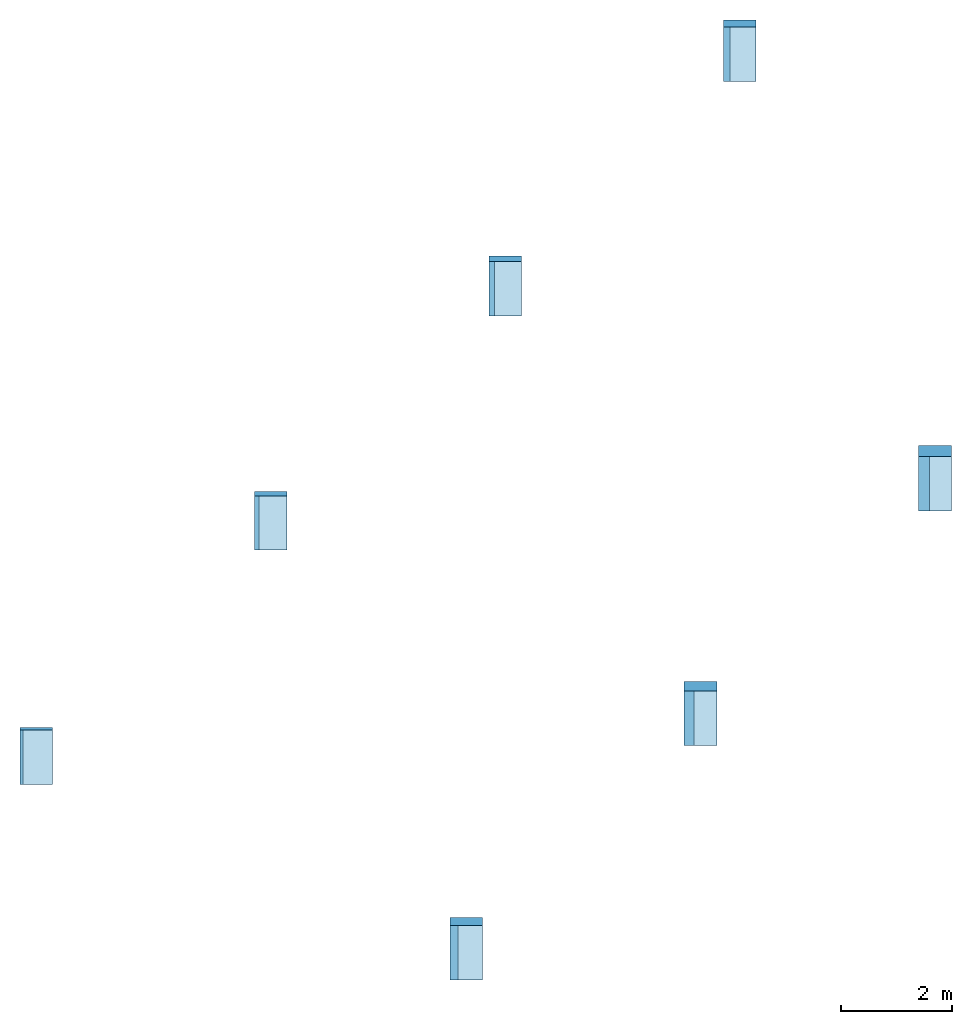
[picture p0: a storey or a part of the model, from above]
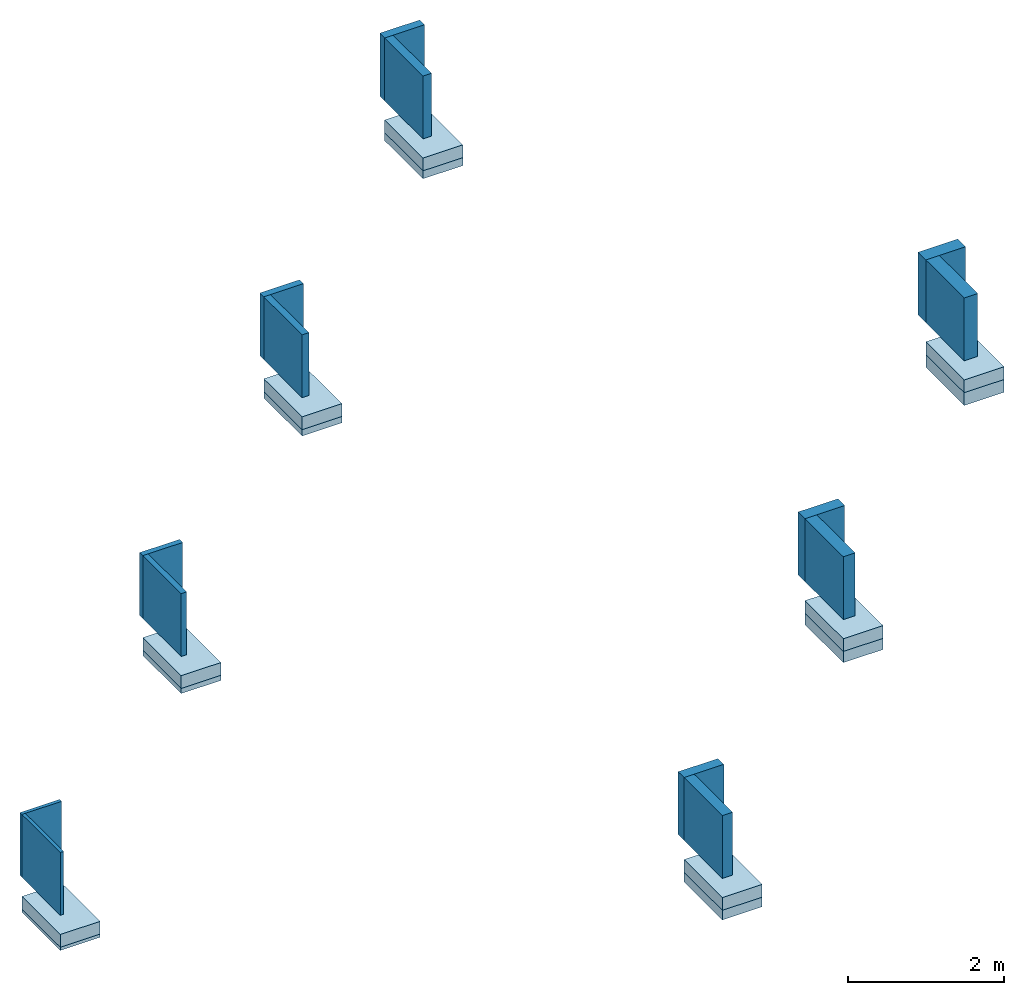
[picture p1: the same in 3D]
Properties of the parts of a building model (IFC2X3), part 1 of 2

# File
Description: ViewDefinition [CoordinationView]
File name: 012345
Time: 2023-01-18T09:47:16
Written by: The EXPRESS Data Manager Version 5.02.0100.07 : 28 Aug 2013
Made in: 21.1.70.21 - Exporter 21.1.70.21 - Alternate UI 21.1.70.21
Comment: STEP Physical File produced by: The EXPRESS Data Manager Version 5.02.0100.07 : 28 Aug 2013 * Module: EDMstepFileFactory/EDMstandAlone * Creation date: Wed Jan 18 09:47:16 2023 * Host: BIM-LT03 * Database: C:\Users\DONNEE~1\AppData\Local\Temp\6dfd9f73-01cb-4fe2-bb7c-203e315a706e\23b874d5-0400-469c-8f44-2d7696e1532f\ifc * Database version: 5507 * Database creation date: Wed Jan 18 09:47:14 2023 * Schema: IFC2X3 * Model: DataRepository.ifc * Model creation date: Wed Jan 18 09:47:15 2023 * Header model: DataRepository.ifc_HeaderModel * Header model creation date: Wed Jan 18 09:47:15 2023 * EDMuser: sdai-user * EDMgroup: sdai-group * License ID and type: 5605 : Permanent license. Expiry date: * EDMstepFileFactory options: 020000

# IfcProject, 012345
LongName: Cadix Project Naam; Phase: Cadix leeg V2.0

# IfcSite, Default
RefLatitude: 52, 3, 20, 225830; RefLongitude: 5, 6, 28, 692855; RefElevation: 0 mm
Pset_ProductRequirements - Category: Project Information

# IfcBuilding
Pset_BuildingCommon - NumberOfStoreys: 2
Pset_ProductRequirements - Category: Project Information

# IfcBuildingStorey: Level:niveau (2)
Pset_ProductRequirements - Category: Levels
Name | LongName = Pset_AirSideSystemInformation, Name = Pset_ProductRequirements, Name | Elevation (mm)
00 begane grond | 00 begane grond | -2.7707e-11
01 eerste verdieping | 01 eerste verdieping | 985

# IfcCovering: Compound Ceiling:NLRS_45_CEI_Heraklith - Heratekta+ 050x590x985mm, Compound Ceiling:NLRS_45_CEI_Heraklith - Heratekta+ 050x590x985mm:915812
In: 01 eerste verdieping
Type - PredefinedType: CEILING
Type - Pset_ConcreteElementGeneral - FireRating: REI 120/180 mits verwerkt.....
Type - Pset_CoveringCommon - Reference: Compound Ceiling:NLRS_45_CEI_Heraklith - Heratekta+ 050x590x985mm; FireRating: REI 120/180 mits verwerkt.....; TotalThickness: 50 mm
Type - Pset_ElementShading - Roughness: 914.4 mm
Type - Pset_ManufacturerTypeInformation - Manufacturer: Knauf Insulation B.V.
Type - Pset_ProductRequirements - Category: Ceilings
Type - Pset_QuantityTakeOff - Reference: Compound Ceiling:NLRS_45_CEI_Heraklith - Heratekta+ 050x590x985mm
Type - Ceiling Schedule LOD200 - Assembly Code: 45; Type Image: Raster image: Heraklith Heratekta.jpg; Model: Heraklith® | Heratekta+ is een houtwolcementpaneel gecombineerd met een EPS-plaat.; Manufacturer: Knauf Insulation B.V.; URL: www.heraklith.nl; Description: Heratekta+ - 50mm; phone: +31(0)162-421245; email: customerservice.nl@knaufinsulation.com; product URL: https://heraklith.nl/houtwol-producten/heratekta-met-EPS; warmteweerstand: 1,40 (m2.K/W); NLRS_C_Code_Brandklasse: B-s1,d0; brandweerstand: n.v.t; geluidsabsorbtie: 0,30; DoP: 4010_HERATEKTA+; NLRS_C_content_creator: Knauf Insulation; NLRS_C_content_versie: V1.0
Type - Pset_Ceiling Schedule LOD400 - gewicht KG/M2: 9; Assembly Code: 45; Type Image: Raster image: Heraklith Heratekta.jpg; Model: Heraklith® | Heratekta+ is een houtwolcementpaneel gecombineerd met een EPS-plaat.; Manufacturer: Knauf Insulation B.V.; URL: www.heraklith.nl; Description: Heratekta+ - 50mm; phone: +31(0)162-421245; email: customerservice.nl@knaufinsulation.com; product URL: https://heraklith.nl/houtwol-producten/heratekta-met-EPS; warmteweerstand: 1,40 (m2.K/W); NLRS_C_Code_Brandklasse: B-s1,d0; brandweerstand: n.v.t; geluidsabsorbtie: 0,30; DoP: 4010_HERATEKTA+; NLRS_C_content_creator: Knauf Insulation; NLRS_C_content_versie: V1.0; panelen per pallet: 44; pallet m2: 25.57 m2; vezelbreedte: standaard 2mm optie: 1mm; kleur: standaard naturel optie: Wit (RAL9003) / RAL; Druksterkte kPa: 40; Chloride gehalte: Cl1; Tolerantie: Dikte (T): (T1) +3/-2; Tolerantie: Lengte (L): (L2) +3/-5; Tolerantie: Breedte (W): (W1) +3/-3; Tolerantie: Haaksheid (S): (S1) ≤4; Tolerantie: Vlakheid (P): (P1) ≤6; Randafwerking: Isolatie: tand en groef; Randafwerking: Houtwol: Facet: 5mm; CE-codering: WW-C/2 EPS-EN13168-L2-W1-S1-T1-P1-CS(10/Y)40-Cl1
Classification: 45 (Uniformat); Material: Heraklith® I Heratekta - EPS60-SE 40 mm, Heraklith® | Heratekta - Houtwollaag - 985x590mm 10 mm
Pset_CoveringCommon - Finish: Heraklith® | Heratekta - Houtwollaag - 985x590mm;
Ceiling Schedule LOD200 - Type: Compound Ceiling: NLRS_45_CEI_Heraklith - Heratekta+ 050x590x985mm
Pset_Ceiling Schedule LOD400 - Type: Compound Ceiling: NLRS_45_CEI_Heraklith - Heratekta+ 050x590x985mm

# IfcCovering: Compound Ceiling:NLRS_45_CEI_Heraklith - Heratekta+ 080x590x985mm, Compound Ceiling:NLRS_45_CEI_Heraklith - Heratekta+ 080x590x985mm:930047
In: 01 eerste verdieping
Type - PredefinedType: CEILING
Type - Pset_CoveringCommon - Reference: Compound Ceiling:NLRS_45_CEI_Heraklith - Heratekta+ 080x590x985mm; TotalThickness: 80 mm
Type - Pset_ElementShading - Roughness: 914.4 mm
Type - Pset_ManufacturerTypeInformation - Manufacturer: Knauf Insulation B.V.
Type - Pset_ProductRequirements - Category: Ceilings
Type - Pset_QuantityTakeOff - Reference: Compound Ceiling:NLRS_45_CEI_Heraklith - Heratekta+ 080x590x985mm
Type - Ceiling Schedule LOD200 - Assembly Code: 45; Type Image: Raster image: Heraklith Heratekta.jpg; Model: Heraklith® | Heratekta+ is een houtwolcementpaneel gecombineerd met een EPS-plaat.; Manufacturer: Knauf Insulation B.V.; URL: www.heraklith.nl; Description: Heratekta+ - 80mm; phone: +31(0)162-421245; email: customerservice.nl@knaufinsulation.com; product URL: https://heraklith.nl/houtwol-producten/heratekta-met-EPS; warmteweerstand: 2,35 (m2.K/W); NLRS_C_Code_Brandklasse: B-s1,d0; brandweerstand: n.v.t; geluidsabsorbtie: 0,30; DoP: 4010_HERATEKTA+; NLRS_C_content_creator: Knauf Insulation; NLRS_C_content_versie: V1.0
Type - Pset_Ceiling Schedule LOD400 - Assembly Code: 45; Type Image: Raster image: Heraklith Heratekta.jpg; Model: Heraklith® | Heratekta+ is een houtwolcementpaneel gecombineerd met een EPS-plaat.; Manufacturer: Knauf Insulation B.V.; URL: www.heraklith.nl; Description: Heratekta+ - 80mm; phone: +31(0)162-421245; email: customerservice.nl@knaufinsulation.com; product URL: https://heraklith.nl/houtwol-producten/heratekta-met-EPS; warmteweerstand: 2,35 (m2.K/W); NLRS_C_Code_Brandklasse: B-s1,d0; brandweerstand: n.v.t; geluidsabsorbtie: 0,30; DoP: 4010_HERATEKTA+; NLRS_C_content_creator: Knauf Insulation; NLRS_C_content_versie: V1.0; gewicht KG/M2: 9.4; panelen per pallet: 26; pallet m2: 15.11 m2; vezelbreedte: standaard 2mm optie: 1mm; kleur: standaard naturel optie: Wit (RAL9003) / RAL; Druksterkte kPa: 40; Chloride gehalte: Cl1; Tolerantie: Dikte (T): (T1) +3/-2; Tolerantie: Lengte (L): (L2) +3/-5; Tolerantie: Breedte (W): (W1) +3/-3; Tolerantie: Haaksheid (S): (S1) ≤4; Tolerantie: Vlakheid (P): (P1) ≤6; Randafwerking: Isolatie: tand en groef; Randafwerking: Houtwol: Facet: 5mm; CE-codering: WW-C/2 EPS-EN13168-L2-W1-S1-T1-P1-CS(10/Y)40-Cl1
Classification: 45 (Uniformat); Material: Heraklith® I Heratekta - EPS60-SE 70 mm, Heraklith® | Heratekta - Houtwollaag - 985x590mm 10 mm
Pset_CoveringCommon - Finish: Heraklith® | Heratekta - Houtwollaag - 985x590mm;
Ceiling Schedule LOD200 - Type: Compound Ceiling: NLRS_45_CEI_Heraklith - Heratekta+ 080x590x985mm
Pset_Ceiling Schedule LOD400 - Type: Compound Ceiling: NLRS_45_CEI_Heraklith - Heratekta+ 080x590x985mm

# IfcCovering: Compound Ceiling:NLRS_45_CEI_Heraklith - Heratekta+ 100x590x985mm, Compound Ceiling:NLRS_45_CEI_Heraklith - Heratekta+ 100x590x985mm:930187
In: 01 eerste verdieping
Type - PredefinedType: CEILING
Type - Pset_CoveringCommon - Reference: Compound Ceiling:NLRS_45_CEI_Heraklith - Heratekta+ 100x590x985mm; TotalThickness: 100 mm
Type - Pset_ElementShading - Roughness: 914.4 mm
Type - Pset_ManufacturerTypeInformation - Manufacturer: Knauf Insulation B.V.
Type - Pset_ProductRequirements - Category: Ceilings
Type - Pset_QuantityTakeOff - Reference: Compound Ceiling:NLRS_45_CEI_Heraklith - Heratekta+ 100x590x985mm
Type - Ceiling Schedule LOD200 - Assembly Code: 45; Type Image: Raster image: Heraklith Heratekta.jpg; Model: Heraklith® | Heratekta+ is een houtwolcementpaneel gecombineerd met een EPS-plaat.; Manufacturer: Knauf Insulation B.V.; URL: www.heraklith.nl; Description: Heratekta+ - 100mm; phone: +31(0)162-421245; email: customerservice.nl@knaufinsulation.com; product URL: https://heraklith.nl/houtwol-producten/heratekta-met-EPS; warmteweerstand: 3,00 (m2.K/W); NLRS_C_Code_Brandklasse: B-s1,d0; brandweerstand: n.v.t; geluidsabsorbtie: 0,30; DoP: 4010_HERATEKTA+; NLRS_C_content_creator: Knauf Insulation; NLRS_C_content_versie: V1.0
Type - Pset_Ceiling Schedule LOD400 - Assembly Code: 45; Type Image: Raster image: Heraklith Heratekta.jpg; Model: Heraklith® | Heratekta+ is een houtwolcementpaneel gecombineerd met een EPS-plaat.; Manufacturer: Knauf Insulation B.V.; URL: www.heraklith.nl; Description: Heratekta+ - 100mm; phone: +31(0)162-421245; email: customerservice.nl@knaufinsulation.com; product URL: https://heraklith.nl/houtwol-producten/heratekta-met-EPS; warmteweerstand: 3,00 (m2.K/W); NLRS_C_Code_Brandklasse: B-s1,d0; brandweerstand: n.v.t; geluidsabsorbtie: 0,30; DoP: 4010_HERATEKTA+; NLRS_C_content_creator: Knauf Insulation; NLRS_C_content_versie: V1.0; gewicht KG/M2: 9.7; panelen per pallet: 22; pallet m2: 12.79 m2; vezelbreedte: standaard 2mm optie: 1mm; kleur: standaard naturel optie: Wit (RAL9003) / RAL; Druksterkte kPa: 40; Chloride gehalte: Cl1; Tolerantie: Dikte (T): (T1) +3/-2; Tolerantie: Lengte (L): (L2) +3/-5; Tolerantie: Breedte (W): (W1) +3/-3; Tolerantie: Haaksheid (S): (S1) ≤4; Tolerantie: Vlakheid (P): (P1) ≤6; Randafwerking: Isolatie: tand en groef; Randafwerking: Houtwol: Facet: 5mm; CE-codering: WW-C/2 EPS-EN13168-L2-W1-S1-T1-P1-CS(10/Y)40-Cl1
Classification: 45 (Uniformat); Material: Heraklith® I Heratekta - EPS60-SE 90 mm, Heraklith® | Heratekta - Houtwollaag - 985x590mm 10 mm
Pset_CoveringCommon - Finish: Heraklith® | Heratekta - Houtwollaag - 985x590mm;
Ceiling Schedule LOD200 - Type: Compound Ceiling: NLRS_45_CEI_Heraklith - Heratekta+ 100x590x985mm
Pset_Ceiling Schedule LOD400 - Type: Compound Ceiling: NLRS_45_CEI_Heraklith - Heratekta+ 100x590x985mm

# IfcCovering: Compound Ceiling:NLRS_45_CEI_Heraklith - Heratekta+ 125x590x985mm, Compound Ceiling:NLRS_45_CEI_Heraklith - Heratekta+ 125x590x985mm:930347
In: 01 eerste verdieping
Type - PredefinedType: CEILING
Type - Pset_CoveringCommon - Reference: Compound Ceiling:NLRS_45_CEI_Heraklith - Heratekta+ 125x590x985mm; TotalThickness: 125 mm
Type - Pset_ElementShading - Roughness: 914.4 mm
Type - Pset_ManufacturerTypeInformation - Manufacturer: Knauf Insulation B.V.
Type - Pset_ProductRequirements - Category: Ceilings
Type - Pset_QuantityTakeOff - Reference: Compound Ceiling:NLRS_45_CEI_Heraklith - Heratekta+ 125x590x985mm
Type - Ceiling Schedule LOD200 - Assembly Code: 45; Type Image: Raster image: Heraklith Heratekta.jpg; Model: Heraklith® | Heratekta+ is een houtwolcementpaneel gecombineerd met een EPS-plaat.; Manufacturer: Knauf Insulation B.V.; URL: www.heraklith.nl; Description: Heratekta+ - 125mm; phone: +31(0)162-421245; email: customerservice.nl@knaufinsulation.com; product URL: https://heraklith.nl/houtwol-producten/heratekta-met-EPS; warmteweerstand: 3,80 (m2.K/W); NLRS_C_Code_Brandklasse: B-s1,d0; brandweerstand: n.v.t; geluidsabsorbtie: 0,30; DoP: 4010_HERATEKTA+; NLRS_C_content_creator: Knauf Insulation; NLRS_C_content_versie: V1.0
Type - Pset_Ceiling Schedule LOD400 - gewicht KG/M2: 10; Assembly Code: 45; Type Image: Raster image: Heraklith Heratekta.jpg; Model: Heraklith® | Heratekta+ is een houtwolcementpaneel gecombineerd met een EPS-plaat.; Manufacturer: Knauf Insulation B.V.; URL: www.heraklith.nl; Description: Heratekta+ - 125mm; phone: +31(0)162-421245; email: customerservice.nl@knaufinsulation.com; product URL: https://heraklith.nl/houtwol-producten/heratekta-met-EPS; warmteweerstand: 3,80 (m2.K/W); NLRS_C_Code_Brandklasse: B-s1,d0; brandweerstand: n.v.t; geluidsabsorbtie: 0,30; DoP: 4010_HERATEKTA+; NLRS_C_content_creator: Knauf Insulation; NLRS_C_content_versie: V1.0; panelen per pallet: 18; pallet m2: 10.46 m2; vezelbreedte: standaard 2mm optie: 1mm; kleur: standaard naturel optie: Wit (RAL9003) / RAL; Druksterkte kPa: 40; Chloride gehalte: Cl1; Tolerantie: Dikte (T): (T1) +3/-2; Tolerantie: Lengte (L): (L2) +3/-5; Tolerantie: Breedte (W): (W1) +3/-3; Tolerantie: Haaksheid (S): (S1) ≤4; Tolerantie: Vlakheid (P): (P1) ≤6; Randafwerking: Isolatie: tand en groef; Randafwerking: Houtwol: Facet: 5mm; CE-codering: WW-C/2 EPS-EN13168-L2-W1-S1-T1-P1-CS(10/Y)40-Cl1
Classification: 45 (Uniformat); Material: Heraklith® I Heratekta - EPS60-SE 115 mm, Heraklith® | Heratekta - Houtwollaag - 985x590mm 10 mm
Pset_CoveringCommon - Finish: Heraklith® | Heratekta - Houtwollaag - 985x590mm;
Ceiling Schedule LOD200 - Type: Compound Ceiling: NLRS_45_CEI_Heraklith - Heratekta+ 125x590x985mm
Pset_Ceiling Schedule LOD400 - Type: Compound Ceiling: NLRS_45_CEI_Heraklith - Heratekta+ 125x590x985mm

# IfcCovering: Compound Ceiling:NLRS_45_CEI_Heraklith - Heratekta+ 150x985x590mm, Compound Ceiling:NLRS_45_CEI_Heraklith - Heratekta+ 150x985x590mm:930587
In: 01 eerste verdieping
Type - PredefinedType: CEILING
Type - Pset_ConcreteElementGeneral - FireRating: REI 120/180 mits verwerkt.....
Type - Pset_CoveringCommon - Reference: Compound Ceiling:NLRS_45_CEI_Heraklith - Heratekta+ 150x985x590mm; FireRating: REI 120/180 mits verwerkt.....; TotalThickness: 150 mm
Type - Pset_ElementShading - Roughness: 914.4 mm
Type - Pset_ManufacturerTypeInformation - Manufacturer: Knauf Insulation B.V.
Type - Pset_ProductRequirements - Category: Ceilings
Type - Pset_QuantityTakeOff - Reference: Compound Ceiling:NLRS_45_CEI_Heraklith - Heratekta+ 150x985x590mm
Type - Ceiling Schedule LOD200 - Assembly Code: 45; Type Image: Raster image: Heraklith Heratekta.jpg; Model: Heraklith® | Heratekta+ is een houtwolcementpaneel gecombineerd met een EPS-plaat.; Manufacturer: Knauf Insulation B.V.; URL: www.heraklith.nl; Description: Heratekta+ - 150mm; phone: +31(0)162-421245; email: customerservice.nl@knaufinsulation.com; product URL: https://heraklith.nl/houtwol-producten/heratekta-met-EPS; warmteweerstand: 4,60 (m2.K/W); NLRS_C_Code_Brandklasse: B-s1,d0; brandweerstand: n.v.t; geluidsabsorbtie: 0,30; DoP: 4010_HERATEKTA+; NLRS_C_content_creator: Knauf Insulation; NLRS_C_content_versie: V1.0
Type - Pset_Ceiling Schedule LOD400 - Assembly Code: 45; Type Image: Raster image: Heraklith Heratekta.jpg; Model: Heraklith® | Heratekta+ is een houtwolcementpaneel gecombineerd met een EPS-plaat.; Manufacturer: Knauf Insulation B.V.; URL: www.heraklith.nl; Description: Heratekta+ - 150mm; phone: +31(0)162-421245; email: customerservice.nl@knaufinsulation.com; product URL: https://heraklith.nl/houtwol-producten/heratekta-met-EPS; warmteweerstand: 4,60 (m2.K/W); NLRS_C_Code_Brandklasse: B-s1,d0; brandweerstand: n.v.t; geluidsabsorbtie: 0,30; DoP: 4010_HERATEKTA+; NLRS_C_content_creator: Knauf Insulation; NLRS_C_content_versie: V1.0; gewicht KG/M2: 10.4; panelen per pallet: 14; pallet m2: 8.14 m2; vezelbreedte: standaard 2mm optie: 1mm; kleur: standaard naturel optie: Wit (RAL9003) / RAL; Druksterkte kPa: 40; Chloride gehalte: Cl1; Tolerantie: Dikte (T): (T1) +3/-2; Tolerantie: Lengte (L): (L2) +3/-5; Tolerantie: Breedte (W): (W1) +3/-3; Tolerantie: Haaksheid (S): (S1) ≤4; Tolerantie: Vlakheid (P): (P1) ≤6; Randafwerking: Isolatie: tand en groef; Randafwerking: Houtwol: Facet: 5mm; CE-codering: WW-C/2 EPS-EN13168-L2-W1-S1-T1-P1-CS(10/Y)40-Cl1
Classification: 45 (Uniformat); Material: Heraklith® I Heratekta - EPS60-SE 140 mm, Heraklith® | Heratekta - Houtwollaag - 985x590mm 10 mm
Pset_CoveringCommon - Finish: Heraklith® | Heratekta - Houtwollaag - 985x590mm;
Ceiling Schedule LOD200 - Type: Compound Ceiling: NLRS_45_CEI_Heraklith - Heratekta+ 150x985x590mm
Pset_Ceiling Schedule LOD400 - Type: Compound Ceiling: NLRS_45_CEI_Heraklith - Heratekta+ 150x985x590mm

# IfcCovering: Compound Ceiling:NLRS_45_CEI_Heraklith - Heratekta+ 175x985x590mm, Compound Ceiling:NLRS_45_CEI_Heraklith - Heratekta+ 175x985x590mm:930687
In: 01 eerste verdieping
Type - PredefinedType: CEILING
Type - Pset_ConcreteElementGeneral - FireRating: REI 120/180 mits verwerkt.....
Type - Pset_CoveringCommon - Reference: Compound Ceiling:NLRS_45_CEI_Heraklith - Heratekta+ 175x985x590mm; FireRating: REI 120/180 mits verwerkt.....; TotalThickness: 175 mm
Type - Pset_ElementShading - Roughness: 914.4 mm
Type - Pset_ManufacturerTypeInformation - Manufacturer: Knauf Insulation B.V.
Type - Pset_ProductRequirements - Category: Ceilings
Type - Pset_QuantityTakeOff - Reference: Compound Ceiling:NLRS_45_CEI_Heraklith - Heratekta+ 175x985x590mm
Type - Ceiling Schedule LOD200 - Assembly Code: 45; Type Image: Raster image: Heraklith Heratekta.jpg; Model: Heraklith® | Heratekta+ is een houtwolcementpaneel gecombineerd met een EPS-plaat.; Manufacturer: Knauf Insulation B.V.; URL: www.heraklith.nl; Description: Heratekta+ - 175mm; phone: +31(0)162-421245; email: customerservice.nl@knaufinsulation.com; product URL: https://heraklith.nl/houtwol-producten/heratekta-met-EPS; warmteweerstand: 5,40 (m2.K/W); NLRS_C_Code_Brandklasse: B-s1,d0; brandweerstand: n.v.t; geluidsabsorbtie: 0,30; DoP: 4010_HERATEKTA+; NLRS_C_content_creator: Knauf Insulation; NLRS_C_content_versie: V1.0
Type - Pset_Ceiling Schedule LOD400 - Assembly Code: 45; Type Image: Raster image: Heraklith Heratekta.jpg; Model: Heraklith® | Heratekta+ is een houtwolcementpaneel gecombineerd met een EPS-plaat.; Manufacturer: Knauf Insulation B.V.; URL: www.heraklith.nl; Description: Heratekta+ - 175mm; phone: +31(0)162-421245; email: customerservice.nl@knaufinsulation.com; product URL: https://heraklith.nl/houtwol-producten/heratekta-met-EPS; warmteweerstand: 5,40 (m2.K/W); NLRS_C_Code_Brandklasse: B-s1,d0; brandweerstand: n.v.t; geluidsabsorbtie: 0,30; DoP: 4010_HERATEKTA+; NLRS_C_content_creator: Knauf Insulation; NLRS_C_content_versie: V1.0; gewicht KG/M2: 10.7; panelen per pallet: 12; pallet m2: 6.97 m2; vezelbreedte: standaard 2mm optie: 1mm; kleur: standaard naturel optie: Wit (RAL9003) / RAL; Druksterkte kPa: 40; Chloride gehalte: Cl1; Tolerantie: Dikte (T): (T1) +3/-2; Tolerantie: Lengte (L): (L2) +3/-5; Tolerantie: Breedte (W): (W1) +3/-3; Tolerantie: Haaksheid (S): (S1) ≤4; Tolerantie: Vlakheid (P): (P1) ≤6; Randafwerking: Isolatie: tand en groef; Randafwerking: Houtwol: Facet: 5mm; CE-codering: WW-C/2 EPS-EN13168-L2-W1-S1-T1-P1-CS(10/Y)40-Cl1
Classification: 45 (Uniformat); Material: Heraklith® I Heratekta - EPS60-SE 165 mm, Heraklith® | Heratekta - Houtwollaag - 985x590mm 10 mm
Pset_CoveringCommon - Finish: Heraklith® | Heratekta - Houtwollaag - 985x590mm;
Ceiling Schedule LOD200 - Type: Compound Ceiling: NLRS_45_CEI_Heraklith - Heratekta+ 175x985x590mm
Pset_Ceiling Schedule LOD400 - Type: Compound Ceiling: NLRS_45_CEI_Heraklith - Heratekta+ 175x985x590mm

# IfcCovering: Compound Ceiling:NLRS_45_CEI_Heraklith - Heratekta+ 200x590x985mm, Compound Ceiling:NLRS_45_CEI_Heraklith - Heratekta+ 200x590x985mm:930867
In: 01 eerste verdieping
Type - PredefinedType: CEILING
Type - Pset_ConcreteElementGeneral - FireRating: REI 120/180 mits verwerkt.....
Type - Pset_CoveringCommon - Reference: Compound Ceiling:NLRS_45_CEI_Heraklith - Heratekta+ 200x590x985mm; FireRating: REI 120/180 mits verwerkt.....; TotalThickness: 200 mm
Type - Pset_ElementShading - Roughness: 914.4 mm
Type - Pset_ManufacturerTypeInformation - Manufacturer: Knauf Insulation B.V.
Type - Pset_ProductRequirements - Category: Ceilings
Type - Pset_QuantityTakeOff - Reference: Compound Ceiling:NLRS_45_CEI_Heraklith - Heratekta+ 200x590x985mm
Type - Ceiling Schedule LOD200 - Assembly Code: 45; Type Image: Raster image: Heraklith Heratekta.jpg; Model: Heraklith® | Heratekta+ is een houtwolcementpaneel gecombineerd met een EPS-plaat.; Manufacturer: Knauf Insulation B.V.; URL: www.heraklith.nl; Description: Heratekta+ - 200mm; phone: +31(0)162-421245; email: customerservice.nl@knaufinsulation.com; product URL: https://heraklith.nl/houtwol-producten/heratekta-met-EPS; warmteweerstand: 6,20 (m2.K/W); NLRS_C_Code_Brandklasse: B-s1,d0; brandweerstand: n.v.t; geluidsabsorbtie: 0,30; DoP: 4010_HERATEKTA+; NLRS_C_content_creator: Knauf Insulation; NLRS_C_content_versie: V1.0
Type - Pset_Ceiling Schedule LOD400 - panelen per pallet: 10; Assembly Code: 45; Type Image: Raster image: Heraklith Heratekta.jpg; Model: Heraklith® | Heratekta+ is een houtwolcementpaneel gecombineerd met een EPS-plaat.; Manufacturer: Knauf Insulation B.V.; URL: www.heraklith.nl; Description: Heratekta+ - 200mm; phone: +31(0)162-421245; email: customerservice.nl@knaufinsulation.com; product URL: https://heraklith.nl/houtwol-producten/heratekta-met-EPS; warmteweerstand: 6,20 (m2.K/W); NLRS_C_Code_Brandklasse: B-s1,d0; brandweerstand: n.v.t; geluidsabsorbtie: 0,30; DoP: 4010_HERATEKTA+; NLRS_C_content_creator: Knauf Insulation; NLRS_C_content_versie: V1.0; gewicht KG/M2: 11.1; pallet m2: 5.81 m2; vezelbreedte: standaard 2mm optie: 1mm; kleur: standaard naturel optie: Wit (RAL9003) / RAL; Druksterkte kPa: 40; Chloride gehalte: Cl1; Tolerantie: Dikte (T): (T1) +3/-2; Tolerantie: Lengte (L): (L2) +3/-5; Tolerantie: Breedte (W): (W1) +3/-3; Tolerantie: Haaksheid (S): (S1) ≤4; Tolerantie: Vlakheid (P): (P1) ≤6; Randafwerking: Isolatie: tand en groef; Randafwerking: Houtwol: Facet: 5mm; CE-codering: WW-C/2 EPS-EN13168-L2-W1-S1-T1-P1-CS(10/Y)40-Cl1
Classification: 45 (Uniformat); Material: Heraklith® I Heratekta - EPS60-SE 190 mm, Heraklith® | Heratekta - Houtwollaag - 985x590mm 10 mm
Pset_CoveringCommon - Finish: Heraklith® | Heratekta - Houtwollaag - 985x590mm;
Ceiling Schedule LOD200 - Type: Compound Ceiling: NLRS_45_CEI_Heraklith - Heratekta+ 200x590x985mm
Pset_Ceiling Schedule LOD400 - Type: Compound Ceiling: NLRS_45_CEI_Heraklith - Heratekta+ 200x590x985mm

# IfcSlab: Floor:Generic 200mm (14)
Type - PredefinedType: FLOOR; Material: Concrete, Precast Panels 200 mm
Type - Pset_ElementShading - Roughness: 914.4 mm
Type - Pset_ProductRequirements - Category: Floors
Type - Pset_QuantityTakeOff - Reference: Floor:Generic 200mm
Type - Pset_ReinforcementBarPitchOfSlab - Reference: Floor:Generic 200mm
Type - Pset_SlabCommon - IsExternal: no; Reference: Floor:Generic 200mm; ThermalTransmittance: 5.23 kg/K/s3
Pset_QuantityTakeOff - sets with these values: 2
Pset_SlabCommon - LoadBearing: no; PitchAngle: 0 deg
Name (Floor:Generic 200mm:...) | In
932520 | 01 eerste verdieping
932549 | 01 eerste verdieping
932578 | 01 eerste verdieping
932603 | 01 eerste verdieping
932630 | 01 eerste verdieping
932657 | 01 eerste verdieping
932689 | 01 eerste verdieping
932734 | 00 begane grond
932778 | 00 begane grond
932798 | 00 begane grond
932814 | 00 begane grond
932830 | 00 begane grond
932846 | 00 begane grond
932862 | 00 begane grond

# IfcSlab: Floor:NLRS_23_FL_Heraklith Heratekta+ 100x985x590mm, Floor:NLRS_23_FL_Heraklith Heratekta+ 100x985x590mm:930194
In: 00 begane grond
Type - PredefinedType: FLOOR; Material: Heraklith® I Heratekta - EPS60-SE 90 mm, Heraklith® | Heratekta - Houtwollaag - 985x590mm 10 mm
Type - Pset_ElementShading - Roughness: 304.8 mm
Type - Pset_ManufacturerTypeInformation - Manufacturer: Knauf Insulation B.V.
Type - Pset_ProductRequirements - Category: Floors
Type - Pset_QuantityTakeOff - Reference: Floor:NLRS_23_FL_Heraklith Heratekta+ 100x985x590mm
Type - Pset_ReinforcementBarPitchOfSlab - Description: Heratekta+ - 100mm; Reference: Floor:NLRS_23_FL_Heraklith Heratekta+ 100x985x590mm
Type - Pset_SlabCommon - IsExternal: no; Reference: Floor:NLRS_23_FL_Heraklith Heratekta+ 100x985x590mm; ThermalTransmittance: 0.342043 kg/K/s3
Type - Floor Schedule LOD200 - Assembly Code: 23.0; Type Image: Raster image: Heraklith Heratekta.jpg; Model: Heraklith® | Heratekta+ is een houtwolcementpaneel gecombineerd met een EPS-plaat.; Manufacturer: Knauf Insulation B.V.; URL: www.heraklith.nl; Description: Heratekta+ - 100mm; phone: +31(0)162-421245; email: customerservice.nl@knaufinsulation.com; product URL: https://heraklith.nl/houtwol-producten/heratekta-met-EPS; warmteweerstand: 3,00 (m2.K/W); NLRS_C_Code_Brandklasse: B-s1,d0; brandweerstand: n.v.t; geluidsabsorbtie: 0,30; DoP: 4010_HERATEKTA+; NLRS_C_content_creator: Knauf Insulation; NLRS_C_content_versie: V1.0
Type - Pset_Floor Schedule LOD400 - Assembly Code: 23.0; Type Image: Raster image: Heraklith Heratekta.jpg; Model: Heraklith® | Heratekta+ is een houtwolcementpaneel gecombineerd met een EPS-plaat.; Manufacturer: Knauf Insulation B.V.; URL: www.heraklith.nl; Description: Heratekta+ - 100mm; phone: +31(0)162-421245; email: customerservice.nl@knaufinsulation.com; product URL: https://heraklith.nl/houtwol-producten/heratekta-met-EPS; warmteweerstand: 3,00 (m2.K/W); NLRS_C_Code_Brandklasse: B-s1,d0; brandweerstand: n.v.t; geluidsabsorbtie: 0,30; DoP: 4010_HERATEKTA+; NLRS_C_content_creator: Knauf Insulation; NLRS_C_content_versie: V1.0; gewicht KG/M2: 9.7; panelen per pallet: 22; pallet m2: 12.79 m2; vezelbreedte: standaard 2mm optie: 1mm; kleur: standaard naturel optie: Wit (RAL9003) / RAL; Druksterkte kPa: 77; Chloride gehalte: Cl1; Tolerantie: Dikte (T): (T1) +3/-2; Tolerantie: Lengte (L): (L2) +3/-5; Tolerantie: Breedte (W): (W1) +3/-3; Tolerantie: Haaksheid (S): (S1) ≤4; Tolerantie: Vlakheid (P): (P1) ≤6; Randafwerking: Isolatie: tand en groef; Randafwerking: Houtwol: Facet: 5mm; CE-codering: WW-C/2 EPS-EN13168-L2-W1-S1-T1-P1-CS(10/Y)40-Cl1
Classification: 23.0 (Uniformat)
Pset_SlabCommon - LoadBearing: no; IsExternal: yes; PitchAngle: 0 deg
Floor Schedule LOD200 - Type: Floor: NLRS_23_FL_Heraklith Heratekta+ 100x985x590mm
Pset_Floor Schedule LOD400 - Type: Floor: NLRS_23_FL_Heraklith Heratekta+ 100x985x590mm

# IfcSlab: Floor:NLRS_23_FL_Heraklith Heratekta+ 125x985x590mm, Floor:NLRS_23_FL_Heraklith Heratekta+ 125x985x590mm:930354
In: 00 begane grond
Type - PredefinedType: FLOOR; Material: Heraklith® I Heratekta - EPS60-SE 115 mm, Heraklith® | Heratekta - Houtwollaag - 985x590mm 10 mm
Type - Pset_ElementShading - Roughness: 304.8 mm
Type - Pset_ManufacturerTypeInformation - Manufacturer: Knauf Insulation B.V.
Type - Pset_ProductRequirements - Category: Floors
Type - Pset_QuantityTakeOff - Reference: Floor:NLRS_23_FL_Heraklith Heratekta+ 125x985x590mm
Type - Pset_ReinforcementBarPitchOfSlab - Description: Heratekta+ - 125mm; Reference: Floor:NLRS_23_FL_Heraklith Heratekta+ 125x985x590mm
Type - Pset_SlabCommon - IsExternal: no; Reference: Floor:NLRS_23_FL_Heraklith Heratekta+ 125x985x590mm; ThermalTransmittance: 0.269916 kg/K/s3
Type - Floor Schedule LOD200 - Assembly Code: 23.0; Type Image: Raster image: Heraklith Heratekta.jpg; Model: Heraklith® | Heratekta+ is een houtwolcementpaneel gecombineerd met een EPS-plaat.; Manufacturer: Knauf Insulation B.V.; URL: www.heraklith.nl; Description: Heratekta+ - 125mm; phone: +31(0)162-421245; email: customerservice.nl@knaufinsulation.com; product URL: https://heraklith.nl/houtwol-producten/heratekta-met-EPS; warmteweerstand: 3,80 (m2.K/W); NLRS_C_Code_Brandklasse: B-s1,d0; brandweerstand: n.v.t; geluidsabsorbtie: 0,30; DoP: 4010_HERATEKTA+; NLRS_C_content_creator: Knauf Insulation; NLRS_C_content_versie: V1.0
Type - Pset_Floor Schedule LOD400 - gewicht KG/M2: 10; Assembly Code: 23.0; Type Image: Raster image: Heraklith Heratekta.jpg; Model: Heraklith® | Heratekta+ is een houtwolcementpaneel gecombineerd met een EPS-plaat.; Manufacturer: Knauf Insulation B.V.; URL: www.heraklith.nl; Description: Heratekta+ - 125mm; phone: +31(0)162-421245; email: customerservice.nl@knaufinsulation.com; product URL: https://heraklith.nl/houtwol-producten/heratekta-met-EPS; warmteweerstand: 3,80 (m2.K/W); NLRS_C_Code_Brandklasse: B-s1,d0; brandweerstand: n.v.t; geluidsabsorbtie: 0,30; DoP: 4010_HERATEKTA+; NLRS_C_content_creator: Knauf Insulation; NLRS_C_content_versie: V1.0; panelen per pallet: 18; pallet m2: 10.46 m2; vezelbreedte: standaard 2mm optie: 1mm; kleur: standaard naturel optie: Wit (RAL9003) / RAL; Druksterkte kPa: 77; Chloride gehalte: Cl1; Tolerantie: Dikte (T): (T1) +3/-2; Tolerantie: Lengte (L): (L2) +3/-5; Tolerantie: Breedte (W): (W1) +3/-3; Tolerantie: Haaksheid (S): (S1) ≤4; Tolerantie: Vlakheid (P): (P1) ≤6; Randafwerking: Isolatie: tand en groef; Randafwerking: Houtwol: Facet: 5mm; CE-codering: WW-C/2 EPS-EN13168-L2-W1-S1-T1-P1-CS(10/Y)40-Cl1
Classification: 23.0 (Uniformat)
Pset_SlabCommon - LoadBearing: no; IsExternal: yes; PitchAngle: 0 deg
Floor Schedule LOD200 - Type: Floor: NLRS_23_FL_Heraklith Heratekta+ 125x985x590mm
Pset_Floor Schedule LOD400 - Type: Floor: NLRS_23_FL_Heraklith Heratekta+ 125x985x590mm

# IfcSlab: Floor:NLRS_23_FL_Heraklith Heratekta+ 150x985x590mm, Floor:NLRS_23_FL_Heraklith Heratekta+ 150x985x590mm:930594
In: 00 begane grond
Type - PredefinedType: FLOOR; Material: Heraklith® I Heratekta - EPS60-SE 140 mm, Heraklith® | Heratekta - Houtwollaag - 985x590mm 10 mm
Type - Pset_ElementShading - Roughness: 304.8 mm
Type - Pset_ManufacturerTypeInformation - Manufacturer: Knauf Insulation B.V.
Type - Pset_ProductRequirements - Category: Floors
Type - Pset_QuantityTakeOff - Reference: Floor:NLRS_23_FL_Heraklith Heratekta+ 150x985x590mm
Type - Pset_ReinforcementBarPitchOfSlab - Description: Heratekta+ - 150mm; Reference: Floor:NLRS_23_FL_Heraklith Heratekta+ 150x985x590mm
Type - Pset_SlabCommon - IsExternal: no; Reference: Floor:NLRS_23_FL_Heraklith Heratekta+ 150x985x590mm; ThermalTransmittance: 0.22291 kg/K/s3
Type - Floor Schedule LOD200 - Assembly Code: 23.0; Type Image: Raster image: Heraklith Heratekta.jpg; Model: Heraklith® | Heratekta+ is een houtwolcementpaneel gecombineerd met een EPS-plaat.; Manufacturer: Knauf Insulation B.V.; URL: www.heraklith.nl; Description: Heratekta+ - 150mm; phone: +31(0)162-421245; email: customerservice.nl@knaufinsulation.com; product URL: https://heraklith.nl/houtwol-producten/heratekta-met-EPS; warmteweerstand: 4,60 (m2.K/W); NLRS_C_Code_Brandklasse: B-s1,d0; brandweerstand: n.v.t; geluidsabsorbtie: 0,30; DoP: 4010_HERATEKTA+; NLRS_C_content_creator: Knauf Insulation; NLRS_C_content_versie: V1.0
Type - Pset_Floor Schedule LOD400 - Assembly Code: 23.0; Type Image: Raster image: Heraklith Heratekta.jpg; Model: Heraklith® | Heratekta+ is een houtwolcementpaneel gecombineerd met een EPS-plaat.; Manufacturer: Knauf Insulation B.V.; URL: www.heraklith.nl; Description: Heratekta+ - 150mm; phone: +31(0)162-421245; email: customerservice.nl@knaufinsulation.com; product URL: https://heraklith.nl/houtwol-producten/heratekta-met-EPS; warmteweerstand: 4,60 (m2.K/W); NLRS_C_Code_Brandklasse: B-s1,d0; brandweerstand: n.v.t; geluidsabsorbtie: 0,30; DoP: 4010_HERATEKTA+; NLRS_C_content_creator: Knauf Insulation; NLRS_C_content_versie: V1.0; gewicht KG/M2: 10.4; panelen per pallet: 14; pallet m2: 8.14 m2; vezelbreedte: standaard 2mm optie: 1mm; kleur: standaard naturel optie: Wit (RAL9003) / RAL; Druksterkte kPa: 77; Chloride gehalte: Cl1; Tolerantie: Dikte (T): (T1) +3/-2; Tolerantie: Lengte (L): (L2) +3/-5; Tolerantie: Breedte (W): (W1) +3/-3; Tolerantie: Haaksheid (S): (S1) ≤4; Tolerantie: Vlakheid (P): (P1) ≤6; Randafwerking: Isolatie: tand en groef; Randafwerking: Houtwol: Facet: 5mm; CE-codering: WW-C/2 EPS-EN13168-L2-W1-S1-T1-P1-CS(10/Y)40-Cl1
Classification: 23.0 (Uniformat)
Pset_SlabCommon - LoadBearing: no; IsExternal: yes; PitchAngle: 0 deg
Floor Schedule LOD200 - Type: Floor: NLRS_23_FL_Heraklith Heratekta+ 150x985x590mm
Pset_Floor Schedule LOD400 - Type: Floor: NLRS_23_FL_Heraklith Heratekta+ 150x985x590mm

# IfcSlab: Floor:NLRS_23_FL_Heraklith Heratekta+ 175x985x590mm, Floor:NLRS_23_FL_Heraklith Heratekta+ 175x985x590mm:930694
In: 00 begane grond
Type - PredefinedType: FLOOR; Material: Heraklith® I Heratekta - EPS60-SE 165 mm, Heraklith® | Heratekta - Houtwollaag - 985x590mm 10 mm
Type - Pset_ElementShading - Roughness: 304.8 mm
Type - Pset_ManufacturerTypeInformation - Manufacturer: Knauf Insulation B.V.
Type - Pset_ProductRequirements - Category: Floors
Type - Pset_QuantityTakeOff - Reference: Floor:NLRS_23_FL_Heraklith Heratekta+ 175x985x590mm
Type - Pset_ReinforcementBarPitchOfSlab - Description: Heratekta+ - 175mm; Reference: Floor:NLRS_23_FL_Heraklith Heratekta+ 175x985x590mm
Type - Pset_SlabCommon - IsExternal: no; Reference: Floor:NLRS_23_FL_Heraklith Heratekta+ 175x985x590mm; ThermalTransmittance: 0.189848 kg/K/s3
Type - Floor Schedule LOD200 - Assembly Code: 23.0; Type Image: Raster image: Heraklith Heratekta.jpg; Model: Heraklith® | Heratekta+ is een houtwolcementpaneel gecombineerd met een EPS-plaat.; Manufacturer: Knauf Insulation B.V.; URL: www.heraklith.nl; Description: Heratekta+ - 175mm; phone: +31(0)162-421245; email: customerservice.nl@knaufinsulation.com; product URL: https://heraklith.nl/houtwol-producten/heratekta-met-EPS; warmteweerstand: 5,40 (m2.K/W); NLRS_C_Code_Brandklasse: B-s1,d0; brandweerstand: n.v.t; geluidsabsorbtie: 0,30; DoP: 4010_HERATEKTA+; NLRS_C_content_creator: Knauf Insulation; NLRS_C_content_versie: V1.0
Type - Pset_Floor Schedule LOD400 - Assembly Code: 23.0; Type Image: Raster image: Heraklith Heratekta.jpg; Model: Heraklith® | Heratekta+ is een houtwolcementpaneel gecombineerd met een EPS-plaat.; Manufacturer: Knauf Insulation B.V.; URL: www.heraklith.nl; Description: Heratekta+ - 175mm; phone: +31(0)162-421245; email: customerservice.nl@knaufinsulation.com; product URL: https://heraklith.nl/houtwol-producten/heratekta-met-EPS; warmteweerstand: 5,40 (m2.K/W); NLRS_C_Code_Brandklasse: B-s1,d0; brandweerstand: n.v.t; geluidsabsorbtie: 0,30; DoP: 4010_HERATEKTA+; NLRS_C_content_creator: Knauf Insulation; NLRS_C_content_versie: V1.0; gewicht KG/M2: 10.7; panelen per pallet: 12; pallet m2: 6.97 m2; vezelbreedte: standaard 2mm optie: 1mm; kleur: standaard naturel optie: Wit (RAL9003) / RAL; Druksterkte kPa: 77; Chloride gehalte: Cl1; Tolerantie: Dikte (T): (T1) +3/-2; Tolerantie: Lengte (L): (L2) +3/-5; Tolerantie: Breedte (W): (W1) +3/-3; Tolerantie: Haaksheid (S): (S1) ≤4; Tolerantie: Vlakheid (P): (P1) ≤6; Randafwerking: Isolatie: tand en groef; Randafwerking: Houtwol: Facet: 5mm; CE-codering: WW-C/2 EPS-EN13168-L2-W1-S1-T1-P1-CS(10/Y)40-Cl1
Classification: 23.0 (Uniformat)
Pset_SlabCommon - LoadBearing: no; IsExternal: yes; PitchAngle: 0 deg
Floor Schedule LOD200 - Type: Floor: NLRS_23_FL_Heraklith Heratekta+ 175x985x590mm
Pset_Floor Schedule LOD400 - Type: Floor: NLRS_23_FL_Heraklith Heratekta+ 175x985x590mm

# IfcSlab: Floor:NLRS_23_FL_Heraklith Heratekta+ 200x985x590mm, Floor:NLRS_23_FL_Heraklith Heratekta+ 200x985x590mm:930874
In: 00 begane grond
Type - PredefinedType: FLOOR; Material: Heraklith® I Heratekta - EPS60-SE 190 mm, Heraklith® | Heratekta - Houtwollaag - 985x590mm 10 mm
Type - Pset_ElementShading - Roughness: 304.8 mm
Type - Pset_ManufacturerTypeInformation - Manufacturer: Knauf Insulation B.V.
Type - Pset_ProductRequirements - Category: Floors
Type - Pset_QuantityTakeOff - Reference: Floor:NLRS_23_FL_Heraklith Heratekta+ 200x985x590mm
Type - Pset_ReinforcementBarPitchOfSlab - Description: Heratekta+ - 200mm; Reference: Floor:NLRS_23_FL_Heraklith Heratekta+ 200x985x590mm
Type - Pset_SlabCommon - IsExternal: no; Reference: Floor:NLRS_23_FL_Heraklith Heratekta+ 200x985x590mm; ThermalTransmittance: 0.165327 kg/K/s3
Type - Floor Schedule LOD200 - Assembly Code: 23.0; Type Image: Raster image: Heraklith Heratekta.jpg; Model: Heraklith® | Heratekta+ is een houtwolcementpaneel gecombineerd met een EPS-plaat.; Manufacturer: Knauf Insulation B.V.; URL: www.heraklith.nl; Description: Heratekta+ - 200mm; phone: +31(0)162-421245; email: customerservice.nl@knaufinsulation.com; product URL: https://heraklith.nl/houtwol-producten/heratekta-met-EPS; warmteweerstand: 6,20 (m2.K/W); NLRS_C_Code_Brandklasse: B-s1,d0; brandweerstand: n.v.t; geluidsabsorbtie: 0,30; DoP: 4010_HERATEKTA+; NLRS_C_content_creator: Knauf Insulation; NLRS_C_content_versie: V1.0
Type - Pset_Floor Schedule LOD400 - panelen per pallet: 10; Assembly Code: 23.0; Type Image: Raster image: Heraklith Heratekta.jpg; Model: Heraklith® | Heratekta+ is een houtwolcementpaneel gecombineerd met een EPS-plaat.; Manufacturer: Knauf Insulation B.V.; URL: www.heraklith.nl; Description: Heratekta+ - 200mm; phone: +31(0)162-421245; email: customerservice.nl@knaufinsulation.com; product URL: https://heraklith.nl/houtwol-producten/heratekta-met-EPS; warmteweerstand: 6,20 (m2.K/W); NLRS_C_Code_Brandklasse: B-s1,d0; brandweerstand: n.v.t; geluidsabsorbtie: 0,30; DoP: 4010_HERATEKTA+; NLRS_C_content_creator: Knauf Insulation; NLRS_C_content_versie: V1.0; gewicht KG/M2: 11.1; pallet m2: 5.81 m2; vezelbreedte: standaard 2mm optie: 1mm; kleur: standaard naturel optie: Wit (RAL9003) / RAL; Druksterkte kPa: 77; Chloride gehalte: Cl1; Tolerantie: Dikte (T): (T1) +3/-2; Tolerantie: Lengte (L): (L2) +3/-5; Tolerantie: Breedte (W): (W1) +3/-3; Tolerantie: Haaksheid (S): (S1) ≤4; Tolerantie: Vlakheid (P): (P1) ≤6; Randafwerking: Isolatie: tand en groef; Randafwerking: Houtwol: Facet: 5mm; CE-codering: WW-C/2 EPS-EN13168-L2-W1-S1-T1-P1-CS(10/Y)40-Cl1
Classification: 23.0 (Uniformat)
Pset_SlabCommon - LoadBearing: no; IsExternal: yes; PitchAngle: 0 deg
Floor Schedule LOD200 - Type: Floor: NLRS_23_FL_Heraklith Heratekta+ 200x985x590mm
Pset_Floor Schedule LOD400 - Type: Floor: NLRS_23_FL_Heraklith Heratekta+ 200x985x590mm

# IfcSlab: Floor:NLRS_23_FL_Heraklith Heratekta+ 50x985x590mm, Floor:NLRS_23_FL_Heraklith Heratekta+ 50x985x590mm:933779
In: 00 begane grond
Type - PredefinedType: FLOOR; Material: Heraklith® I Heratekta - EPS60-SE 40 mm, Heraklith® | Heratekta - Houtwollaag - 985x590mm 10 mm
Type - Pset_ElementShading - Roughness: 304.8 mm
Type - Pset_ManufacturerTypeInformation - Manufacturer: Knauf Insulation B.V.
Type - Pset_ProductRequirements - Category: Floors
Type - Pset_QuantityTakeOff - Reference: Floor:NLRS_23_FL_Heraklith Heratekta+ 50x985x590mm
Type - Pset_ReinforcementBarPitchOfSlab - Description: Heratekta+ - 50mm; Reference: Floor:NLRS_23_FL_Heraklith Heratekta+ 50x985x590mm
Type - Pset_SlabCommon - IsExternal: no; Reference: Floor:NLRS_23_FL_Heraklith Heratekta+ 50x985x590mm; ThermalTransmittance: 0.734694 kg/K/s3
Type - Floor Schedule LOD200 - Assembly Code: 23.0; Type Image: Raster image: Heraklith Heratekta.jpg; Model: Heraklith® | Heratekta+ is een houtwolcementpaneel gecombineerd met een EPS-plaat.; Manufacturer: Knauf Insulation B.V.; URL: www.heraklith.nl; Description: Heratekta+ - 50mm; phone: +31(0)162-421245; email: customerservice.nl@knaufinsulation.com; product URL: https://heraklith.nl/houtwol-producten/heratekta-met-EPS; warmteweerstand: 1,40 (m2.K/W); NLRS_C_Code_Brandklasse: B-s1,d0; brandweerstand: n.v.t; geluidsabsorbtie: 0,30; DoP: 4010_HERATEKTA+; NLRS_C_content_creator: Knauf Insulation; NLRS_C_content_versie: V1.0
Type - Pset_Floor Schedule LOD400 - gewicht KG/M2: 9; Assembly Code: 23.0; Type Image: Raster image: Heraklith Heratekta.jpg; Model: Heraklith® | Heratekta+ is een houtwolcementpaneel gecombineerd met een EPS-plaat.; Manufacturer: Knauf Insulation B.V.; URL: www.heraklith.nl; Description: Heratekta+ - 50mm; phone: +31(0)162-421245; email: customerservice.nl@knaufinsulation.com; product URL: https://heraklith.nl/houtwol-producten/heratekta-met-EPS; warmteweerstand: 1,40 (m2.K/W); NLRS_C_Code_Brandklasse: B-s1,d0; brandweerstand: n.v.t; geluidsabsorbtie: 0,30; DoP: 4010_HERATEKTA+; NLRS_C_content_creator: Knauf Insulation; NLRS_C_content_versie: V1.0; panelen per pallet: 44; pallet m2: 25.57 m2; vezelbreedte: standaard 2mm optie: 1mm; kleur: standaard naturel optie: Wit (RAL9003) / RAL; Druksterkte kPa: 77; Chloride gehalte: Cl1; Tolerantie: Dikte (T): (T1) +3/-2; Tolerantie: Lengte (L): (L2) +3/-5; Tolerantie: Breedte (W): (W1) +3/-3; Tolerantie: Haaksheid (S): (S1) ≤4; Tolerantie: Vlakheid (P): (P1) ≤6; Randafwerking: Isolatie: tand en groef; Randafwerking: Houtwol: Facet: 5mm; CE-codering: WW-C/2 EPS-EN13168-L2-W1-S1-T1-P1-CS(10/Y)40-Cl1
Classification: 23.0 (Uniformat)
Pset_SlabCommon - LoadBearing: no; IsExternal: yes; PitchAngle: 0 deg
Floor Schedule LOD200 - Type: Floor: NLRS_23_FL_Heraklith Heratekta+ 50x985x590mm
Pset_Floor Schedule LOD400 - Type: Floor: NLRS_23_FL_Heraklith Heratekta+ 50x985x590mm

# IfcSlab: Floor:NLRS_23_FL_Heraklith Heratekta+ 80x985x590mm, Floor:NLRS_23_FL_Heraklith Heratekta+ 80x985x590mm:930054
In: 00 begane grond
Type - PredefinedType: FLOOR; Material: Heraklith® I Heratekta - EPS60-SE 70 mm, Heraklith® | Heratekta - Houtwollaag - 985x590mm 10 mm
Type - Pset_ElementShading - Roughness: 304.8 mm
Type - Pset_ManufacturerTypeInformation - Manufacturer: Knauf Insulation B.V.
Type - Pset_ProductRequirements - Category: Floors
Type - Pset_QuantityTakeOff - Reference: Floor:NLRS_23_FL_Heraklith Heratekta+ 80x985x590mm
Type - Pset_ReinforcementBarPitchOfSlab - Description: Heratekta+ - 80mm; Reference: Floor:NLRS_23_FL_Heraklith Heratekta+ 80x985x590mm
Type - Pset_SlabCommon - IsExternal: no; Reference: Floor:NLRS_23_FL_Heraklith Heratekta+ 80x985x590mm; ThermalTransmittance: 0.435045 kg/K/s3
Type - Floor Schedule LOD200 - Assembly Code: 23.0; Type Image: Raster image: Heraklith Heratekta.jpg; Model: Heraklith® | Heratekta+ is een houtwolcementpaneel gecombineerd met een EPS-plaat.; Manufacturer: Knauf Insulation B.V.; URL: www.heraklith.nl; Description: Heratekta+ - 80mm; phone: +31(0)162-421245; email: customerservice.nl@knaufinsulation.com; product URL: https://heraklith.nl/houtwol-producten/heratekta-met-EPS; warmteweerstand: 2,35 (m2.K/W); NLRS_C_Code_Brandklasse: B-s1,d0; brandweerstand: n.v.t; geluidsabsorbtie: 0,30; DoP: 4010_HERATEKTA+; NLRS_C_content_creator: Knauf Insulation; NLRS_C_content_versie: V1.0
Type - Pset_Floor Schedule LOD400 - Assembly Code: 23.0; Type Image: Raster image: Heraklith Heratekta.jpg; Model: Heraklith® | Heratekta+ is een houtwolcementpaneel gecombineerd met een EPS-plaat.; Manufacturer: Knauf Insulation B.V.; URL: www.heraklith.nl; Description: Heratekta+ - 80mm; phone: +31(0)162-421245; email: customerservice.nl@knaufinsulation.com; product URL: https://heraklith.nl/houtwol-producten/heratekta-met-EPS; warmteweerstand: 2,35 (m2.K/W); NLRS_C_Code_Brandklasse: B-s1,d0; brandweerstand: n.v.t; geluidsabsorbtie: 0,30; DoP: 4010_HERATEKTA+; NLRS_C_content_creator: Knauf Insulation; NLRS_C_content_versie: V1.0; gewicht KG/M2: 9.4; panelen per pallet: 26; pallet m2: 15.11 m2; vezelbreedte: standaard 2mm optie: 1mm; kleur: standaard naturel optie: Wit (RAL9003) / RAL; Druksterkte kPa: 77; Chloride gehalte: Cl1; Tolerantie: Dikte (T): (T1) +3/-2; Tolerantie: Lengte (L): (L2) +3/-5; Tolerantie: Breedte (W): (W1) +3/-3; Tolerantie: Haaksheid (S): (S1) ≤4; Tolerantie: Vlakheid (P): (P1) ≤6; Randafwerking: Isolatie: tand en groef; Randafwerking: Houtwol: Facet: 5mm; CE-codering: WW-C/2 EPS-EN13168-L2-W1-S1-T1-P1-CS(10/Y)40-Cl1
Classification: 23.0 (Uniformat)
Pset_SlabCommon - LoadBearing: no; IsExternal: yes; PitchAngle: 0 deg
Floor Schedule LOD200 - Type: Floor: NLRS_23_FL_Heraklith Heratekta+ 80x985x590mm
Pset_Floor Schedule LOD400 - Type: Floor: NLRS_23_FL_Heraklith Heratekta+ 80x985x590mm

# IfcWallStandardCase: Basic Wall:NLRS_41_WA_Heraklith Heratekta+ 100x985x590mm, Basic Wall:NLRS_41_WA_Heraklith Heratekta+ 100x985x590mm:930202
In: 00 begane grond
Type - PredefinedType: STANDARD; Material: Heraklith® I Heratekta - EPS60-SE 90 mm, Heraklith® | Heratekta - Houtwollaag - 985x590mm 10 mm
Type - Pset_ElementShading - Roughness: 304.8 mm
Type - Pset_ManufacturerTypeInformation - Manufacturer: Knauf Insulation B.V.
Type - Pset_ProductRequirements - Category: Walls
Type - Pset_QuantityTakeOff - Reference: Basic Wall:NLRS_41_WA_Heraklith Heratekta+ 100x985x590mm
Type - Pset_ReinforcementBarPitchOfWall - Description: Heratekta+ - 100mm; Reference: Basic Wall:NLRS_41_WA_Heraklith Heratekta+ 100x985x590mm
Type - Pset_WallCommon - IsExternal: no; Reference: Basic Wall:NLRS_41_WA_Heraklith Heratekta+ 100x985x590mm; ThermalTransmittance: 0.342043 kg/K/s3
Type - Wall Schedule LOD200 - Assembly Code: 41.10; Type Image: Raster image: Heraklith Heratekta.jpg; Model: Heraklith® | Heratekta+ is een houtwolcementpaneel gecombineerd met een EPS-plaat.; Manufacturer: Knauf Insulation B.V.; URL: www.heraklith.nl; Description: Heratekta+ - 100mm; phone: +31(0)162-421245; email: customerservice.nl@knaufinsulation.com; product URL: https://heraklith.nl/houtwol-producten/heratekta-met-EPS; warmteweerstand: 3,00 (m2.K/W); NLRS_C_Code_Brandklasse: B-s1,d0; brandweerstand: n.v.t; geluidsabsorbtie: 0,30; DoP: 4010_HERATEKTA+; NLRS_C_content_creator: Knauf Insulation; NLRS_C_content_versie: V1.0
Type - Pset_Wall Schedule LOD400 - Assembly Code: 41.10; Type Image: Raster image: Heraklith Heratekta.jpg; Model: Heraklith® | Heratekta+ is een houtwolcementpaneel gecombineerd met een EPS-plaat.; Manufacturer: Knauf Insulation B.V.; URL: www.heraklith.nl; Description: Heratekta+ - 100mm; phone: +31(0)162-421245; email: customerservice.nl@knaufinsulation.com; product URL: https://heraklith.nl/houtwol-producten/heratekta-met-EPS; warmteweerstand: 3,00 (m2.K/W); NLRS_C_Code_Brandklasse: B-s1,d0; brandweerstand: n.v.t; geluidsabsorbtie: 0,30; DoP: 4010_HERATEKTA+; NLRS_C_content_creator: Knauf Insulation; NLRS_C_content_versie: V1.0; gewicht KG/M2: 9.7; panelen per pallet: 22; pallet m2: 12.79 m2; vezelbreedte: standaard 2mm optie: 1mm; kleur: standaard naturel optie: Wit (RAL9003) / RAL; Druksterkte kPa: 40; Chloride gehalte: Cl1; Tolerantie: Dikte (T): (T1) +3/-2; Tolerantie: Lengte (L): (L2) +3/-5; Tolerantie: Breedte (W): (W1) +3/-3; Tolerantie: Haaksheid (S): (S1) ≤4; Tolerantie: Vlakheid (P): (P1) ≤6; Randafwerking: Isolatie: tand en groef; Randafwerking: Houtwol: Facet: 5mm; CE-codering: WW-C/2 EPS-EN13168-L2-W1-S1-T1-P1-CS(10/Y)40-Cl1
Classification: 41.10 (Uniformat)
Pset_WallCommon - ExtendToStructure: no; LoadBearing: no; IsExternal: yes
Wall Schedule LOD200 - Type: Basic Wall: NLRS_41_WA_Heraklith Heratekta+ 100x985x590mm
Pset_Wall Schedule LOD400 - Type: Basic Wall: NLRS_41_WA_Heraklith Heratekta+ 100x985x590mm

# IfcWallStandardCase: Basic Wall:NLRS_41_WA_Heraklith Heratekta+ 125x985x590mm, Basic Wall:NLRS_41_WA_Heraklith Heratekta+ 125x985x590mm:930362
In: 00 begane grond
Type - PredefinedType: STANDARD; Material: Heraklith® I Heratekta - EPS60-SE 115 mm, Heraklith® | Heratekta - Houtwollaag - 985x590mm 10 mm
Type - Pset_ElementShading - Roughness: 304.8 mm
Type - Pset_ManufacturerTypeInformation - Manufacturer: Knauf Insulation B.V.
Type - Pset_ProductRequirements - Category: Walls
Type - Pset_QuantityTakeOff - Reference: Basic Wall:NLRS_41_WA_Heraklith Heratekta+ 125x985x590mm
Type - Pset_ReinforcementBarPitchOfWall - Description: Heratekta+ - 125mm; Reference: Basic Wall:NLRS_41_WA_Heraklith Heratekta+ 125x985x590mm
Type - Pset_WallCommon - IsExternal: no; Reference: Basic Wall:NLRS_41_WA_Heraklith Heratekta+ 125x985x590mm; ThermalTransmittance: 0.269916 kg/K/s3
Type - Wall Schedule LOD200 - Assembly Code: 41.10; Type Image: Raster image: Heraklith Heratekta.jpg; Model: Heraklith® | Heratekta+ is een houtwolcementpaneel gecombineerd met een EPS-plaat.; Manufacturer: Knauf Insulation B.V.; URL: www.heraklith.nl; Description: Heratekta+ - 125mm; phone: +31(0)162-421245; email: customerservice.nl@knaufinsulation.com; product URL: https://heraklith.nl/houtwol-producten/heratekta-met-EPS; warmteweerstand: 3,80 (m2.K/W); NLRS_C_Code_Brandklasse: B-s1,d0; brandweerstand: n.v.t; geluidsabsorbtie: 0,30; DoP: 4010_HERATEKTA+; NLRS_C_content_creator: Knauf Insulation; NLRS_C_content_versie: V1.0
Type - Pset_Wall Schedule LOD400 - gewicht KG/M2: 10; Assembly Code: 41.10; Type Image: Raster image: Heraklith Heratekta.jpg; Model: Heraklith® | Heratekta+ is een houtwolcementpaneel gecombineerd met een EPS-plaat.; Manufacturer: Knauf Insulation B.V.; URL: www.heraklith.nl; Description: Heratekta+ - 125mm; phone: +31(0)162-421245; email: customerservice.nl@knaufinsulation.com; product URL: https://heraklith.nl/houtwol-producten/heratekta-met-EPS; warmteweerstand: 3,80 (m2.K/W); NLRS_C_Code_Brandklasse: B-s1,d0; brandweerstand: n.v.t; geluidsabsorbtie: 0,30; DoP: 4010_HERATEKTA+; NLRS_C_content_creator: Knauf Insulation; NLRS_C_content_versie: V1.0; panelen per pallet: 18; pallet m2: 10.46 m2; vezelbreedte: standaard 2mm optie: 1mm; kleur: standaard naturel optie: Wit (RAL9003) / RAL; Druksterkte kPa: 40; Chloride gehalte: Cl1; Tolerantie: Dikte (T): (T1) +3/-2; Tolerantie: Lengte (L): (L2) +3/-5; Tolerantie: Breedte (W): (W1) +3/-3; Tolerantie: Haaksheid (S): (S1) ≤4; Tolerantie: Vlakheid (P): (P1) ≤6; Randafwerking: Isolatie: tand en groef; Randafwerking: Houtwol: Facet: 5mm; CE-codering: WW-C/2 EPS-EN13168-L2-W1-S1-T1-P1-CS(10/Y)40-Cl1
Classification: 41.10 (Uniformat)
Pset_WallCommon - ExtendToStructure: no; LoadBearing: no; IsExternal: yes
Wall Schedule LOD200 - Type: Basic Wall: NLRS_41_WA_Heraklith Heratekta+ 125x985x590mm
Pset_Wall Schedule LOD400 - Type: Basic Wall: NLRS_41_WA_Heraklith Heratekta+ 125x985x590mm

# IfcWallStandardCase: Basic Wall:NLRS_41_WA_Heraklith Heratekta+ 150x985x590mm, Basic Wall:NLRS_41_WA_Heraklith Heratekta+ 150x985x590mm:930602
In: 00 begane grond
Type - PredefinedType: STANDARD; Material: Heraklith® I Heratekta - EPS60-SE 140 mm, Heraklith® | Heratekta - Houtwollaag - 985x590mm 10 mm
Type - Pset_ElementShading - Roughness: 304.8 mm
Type - Pset_ManufacturerTypeInformation - Manufacturer: Knauf Insulation B.V.
Type - Pset_ProductRequirements - Category: Walls
Type - Pset_QuantityTakeOff - Reference: Basic Wall:NLRS_41_WA_Heraklith Heratekta+ 150x985x590mm
Type - Pset_ReinforcementBarPitchOfWall - Description: Heratekta+ - 150mm; Reference: Basic Wall:NLRS_41_WA_Heraklith Heratekta+ 150x985x590mm
Type - Pset_WallCommon - IsExternal: no; Reference: Basic Wall:NLRS_41_WA_Heraklith Heratekta+ 150x985x590mm; ThermalTransmittance: 0.22291 kg/K/s3
Type - Wall Schedule LOD200 - Assembly Code: 41.10; Type Image: Raster image: Heraklith Heratekta.jpg; Model: Heraklith® | Heratekta+ is een houtwolcementpaneel gecombineerd met een EPS-plaat.; Manufacturer: Knauf Insulation B.V.; URL: www.heraklith.nl; Description: Heratekta+ - 150mm; phone: +31(0)162-421245; email: customerservice.nl@knaufinsulation.com; product URL: https://heraklith.nl/houtwol-producten/heratekta-met-EPS; warmteweerstand: 4,60 (m2.K/W); NLRS_C_Code_Brandklasse: B-s1,d0; brandweerstand: n.v.t; geluidsabsorbtie: 0,30; DoP: 4010_HERATEKTA+; NLRS_C_content_creator: Knauf Insulation; NLRS_C_content_versie: V1.0
Type - Pset_Wall Schedule LOD400 - Assembly Code: 41.10; Type Image: Raster image: Heraklith Heratekta.jpg; Model: Heraklith® | Heratekta+ is een houtwolcementpaneel gecombineerd met een EPS-plaat.; Manufacturer: Knauf Insulation B.V.; URL: www.heraklith.nl; Description: Heratekta+ - 150mm; phone: +31(0)162-421245; email: customerservice.nl@knaufinsulation.com; product URL: https://heraklith.nl/houtwol-producten/heratekta-met-EPS; warmteweerstand: 4,60 (m2.K/W); NLRS_C_Code_Brandklasse: B-s1,d0; brandweerstand: n.v.t; geluidsabsorbtie: 0,30; DoP: 4010_HERATEKTA+; NLRS_C_content_creator: Knauf Insulation; NLRS_C_content_versie: V1.0; gewicht KG/M2: 10.4; panelen per pallet: 14; pallet m2: 8.14 m2; vezelbreedte: standaard 2mm optie: 1mm; kleur: standaard naturel optie: Wit (RAL9003) / RAL; Druksterkte kPa: 40; Chloride gehalte: Cl1; Tolerantie: Dikte (T): (T1) +3/-2; Tolerantie: Lengte (L): (L2) +3/-5; Tolerantie: Breedte (W): (W1) +3/-3; Tolerantie: Haaksheid (S): (S1) ≤4; Tolerantie: Vlakheid (P): (P1) ≤6; Randafwerking: Isolatie: tand en groef; Randafwerking: Houtwol: Facet: 5mm; CE-codering: WW-C/2 EPS-EN13168-L2-W1-S1-T1-P1-CS(10/Y)40-Cl1
Classification: 41.10 (Uniformat)
Pset_WallCommon - ExtendToStructure: no; LoadBearing: no; IsExternal: yes
Wall Schedule LOD200 - Type: Basic Wall: NLRS_41_WA_Heraklith Heratekta+ 150x985x590mm
Pset_Wall Schedule LOD400 - Type: Basic Wall: NLRS_41_WA_Heraklith Heratekta+ 150x985x590mm

# IfcWallStandardCase: Basic Wall:NLRS_41_WA_Heraklith Heratekta+ 175x985x590mm, Basic Wall:NLRS_41_WA_Heraklith Heratekta+ 175x985x590mm:930702
In: 00 begane grond
Type - PredefinedType: STANDARD; Material: Heraklith® I Heratekta - EPS60-SE 165 mm, Heraklith® | Heratekta - Houtwollaag - 985x590mm 10 mm
Type - Pset_ElementShading - Roughness: 304.8 mm
Type - Pset_ManufacturerTypeInformation - Manufacturer: Knauf Insulation B.V.
Type - Pset_ProductRequirements - Category: Walls
Type - Pset_QuantityTakeOff - Reference: Basic Wall:NLRS_41_WA_Heraklith Heratekta+ 175x985x590mm
Type - Pset_ReinforcementBarPitchOfWall - Description: Heratekta+ - 175mm; Reference: Basic Wall:NLRS_41_WA_Heraklith Heratekta+ 175x985x590mm
Type - Pset_WallCommon - IsExternal: no; Reference: Basic Wall:NLRS_41_WA_Heraklith Heratekta+ 175x985x590mm; ThermalTransmittance: 0.189848 kg/K/s3
Type - Wall Schedule LOD200 - Assembly Code: 41.10; Type Image: Raster image: Heraklith Heratekta.jpg; Model: Heraklith® | Heratekta+ is een houtwolcementpaneel gecombineerd met een EPS-plaat.; Manufacturer: Knauf Insulation B.V.; URL: www.heraklith.nl; Description: Heratekta+ - 175mm; phone: +31(0)162-421245; email: customerservice.nl@knaufinsulation.com; product URL: https://heraklith.nl/houtwol-producten/heratekta-met-EPS; warmteweerstand: 5,40 (m2.K/W); NLRS_C_Code_Brandklasse: B-s1,d0; brandweerstand: n.v.t; geluidsabsorbtie: 0,30; DoP: 4010_HERATEKTA+; NLRS_C_content_creator: Knauf Insulation; NLRS_C_content_versie: V1.0
Type - Pset_Wall Schedule LOD400 - Assembly Code: 41.10; Type Image: Raster image: Heraklith Heratekta.jpg; Model: Heraklith® | Heratekta+ is een houtwolcementpaneel gecombineerd met een EPS-plaat.; Manufacturer: Knauf Insulation B.V.; URL: www.heraklith.nl; Description: Heratekta+ - 175mm; phone: +31(0)162-421245; email: customerservice.nl@knaufinsulation.com; product URL: https://heraklith.nl/houtwol-producten/heratekta-met-EPS; warmteweerstand: 5,40 (m2.K/W); NLRS_C_Code_Brandklasse: B-s1,d0; brandweerstand: n.v.t; geluidsabsorbtie: 0,30; DoP: 4010_HERATEKTA+; NLRS_C_content_creator: Knauf Insulation; NLRS_C_content_versie: V1.0; gewicht KG/M2: 10.7; panelen per pallet: 12; pallet m2: 6.97 m2; vezelbreedte: standaard 2mm optie: 1mm; kleur: standaard naturel optie: Wit (RAL9003) / RAL; Druksterkte kPa: 40; Chloride gehalte: Cl1; Tolerantie: Dikte (T): (T1) +3/-2; Tolerantie: Lengte (L): (L2) +3/-5; Tolerantie: Breedte (W): (W1) +3/-3; Tolerantie: Haaksheid (S): (S1) ≤4; Tolerantie: Vlakheid (P): (P1) ≤6; Randafwerking: Isolatie: tand en groef; Randafwerking: Houtwol: Facet: 5mm; CE-codering: WW-C/2 EPS-EN13168-L2-W1-S1-T1-P1-CS(10/Y)40-Cl1
Classification: 41.10 (Uniformat)
Pset_WallCommon - ExtendToStructure: no; LoadBearing: no; IsExternal: yes
Wall Schedule LOD200 - Type: Basic Wall: NLRS_41_WA_Heraklith Heratekta+ 175x985x590mm
Pset_Wall Schedule LOD400 - Type: Basic Wall: NLRS_41_WA_Heraklith Heratekta+ 175x985x590mm

# IfcWallStandardCase: Basic Wall:NLRS_41_WA_Heraklith Heratekta+ 200x985x590mm, Basic Wall:NLRS_41_WA_Heraklith Heratekta+ 200x985x590mm:930882
In: 00 begane grond
Type - PredefinedType: STANDARD; Material: Heraklith® I Heratekta - EPS60-SE 190 mm, Heraklith® | Heratekta - Houtwollaag - 985x590mm 10 mm
Type - Pset_ElementShading - Roughness: 304.8 mm
Type - Pset_ManufacturerTypeInformation - Manufacturer: Knauf Insulation B.V.
Type - Pset_ProductRequirements - Category: Walls
Type - Pset_QuantityTakeOff - Reference: Basic Wall:NLRS_41_WA_Heraklith Heratekta+ 200x985x590mm
Type - Pset_ReinforcementBarPitchOfWall - Description: Heratekta+ - 200mm; Reference: Basic Wall:NLRS_41_WA_Heraklith Heratekta+ 200x985x590mm
Type - Pset_WallCommon - IsExternal: no; Reference: Basic Wall:NLRS_41_WA_Heraklith Heratekta+ 200x985x590mm; ThermalTransmittance: 0.165327 kg/K/s3
Type - Wall Schedule LOD200 - Assembly Code: 41.10; Type Image: Raster image: Heraklith Heratekta.jpg; Model: Heraklith® | Heratekta+ is een houtwolcementpaneel gecombineerd met een EPS-plaat.; Manufacturer: Knauf Insulation B.V.; URL: www.heraklith.nl; Description: Heratekta+ - 200mm; phone: +31(0)162-421245; email: customerservice.nl@knaufinsulation.com; product URL: https://heraklith.nl/houtwol-producten/heratekta-met-EPS; warmteweerstand: 6,20 (m2.K/W); NLRS_C_Code_Brandklasse: B-s1,d0; brandweerstand: n.v.t; geluidsabsorbtie: 0,30; DoP: 4010_HERATEKTA+; NLRS_C_content_creator: Knauf Insulation; NLRS_C_content_versie: V1.0
Type - Pset_Wall Schedule LOD400 - panelen per pallet: 10; Assembly Code: 41.10; Type Image: Raster image: Heraklith Heratekta.jpg; Model: Heraklith® | Heratekta+ is een houtwolcementpaneel gecombineerd met een EPS-plaat.; Manufacturer: Knauf Insulation B.V.; URL: www.heraklith.nl; Description: Heratekta+ - 200mm; phone: +31(0)162-421245; email: customerservice.nl@knaufinsulation.com; product URL: https://heraklith.nl/houtwol-producten/heratekta-met-EPS; warmteweerstand: 6,20 (m2.K/W); NLRS_C_Code_Brandklasse: B-s1,d0; brandweerstand: n.v.t; geluidsabsorbtie: 0,30; DoP: 4010_HERATEKTA+; NLRS_C_content_creator: Knauf Insulation; NLRS_C_content_versie: V1.0; gewicht KG/M2: 11.1; pallet m2: 5.81 m2; vezelbreedte: standaard 2mm optie: 1mm; kleur: standaard naturel optie: Wit (RAL9003) / RAL; Druksterkte kPa: 40; Chloride gehalte: Cl1; Tolerantie: Dikte (T): (T1) +3/-2; Tolerantie: Lengte (L): (L2) +3/-5; Tolerantie: Breedte (W): (W1) +3/-3; Tolerantie: Haaksheid (S): (S1) ≤4; Tolerantie: Vlakheid (P): (P1) ≤6; Randafwerking: Isolatie: tand en groef; Randafwerking: Houtwol: Facet: 5mm; CE-codering: WW-C/2 EPS-EN13168-L2-W1-S1-T1-P1-CS(10/Y)40-Cl1
Classification: 41.10 (Uniformat)
Pset_WallCommon - ExtendToStructure: no; LoadBearing: no; IsExternal: yes
Wall Schedule LOD200 - Type: Basic Wall: NLRS_41_WA_Heraklith Heratekta+ 200x985x590mm
Pset_Wall Schedule LOD400 - Type: Basic Wall: NLRS_41_WA_Heraklith Heratekta+ 200x985x590mm

# IfcWallStandardCase: Basic Wall:NLRS_41_WA_Heraklith Heratekta+ 50x985x590mm, Basic Wall:NLRS_41_WA_Heraklith Heratekta+ 50x985x590mm:928375
In: 00 begane grond
Type - PredefinedType: STANDARD; Material: Heraklith® I Heratekta - EPS60-SE 40 mm, Heraklith® | Heratekta - Houtwollaag - 985x590mm 10 mm
Type - Pset_ElementShading - Roughness: 304.8 mm
Type - Pset_ManufacturerTypeInformation - Manufacturer: Knauf Insulation B.V.
Type - Pset_ProductRequirements - Category: Walls
Type - Pset_QuantityTakeOff - Reference: Basic Wall:NLRS_41_WA_Heraklith Heratekta+ 50x985x590mm
Type - Pset_ReinforcementBarPitchOfWall - Description: Heratekta+ - 50mm; Reference: Basic Wall:NLRS_41_WA_Heraklith Heratekta+ 50x985x590mm
Type - Pset_WallCommon - IsExternal: no; Reference: Basic Wall:NLRS_41_WA_Heraklith Heratekta+ 50x985x590mm; ThermalTransmittance: 0.734694 kg/K/s3
Type - Wall Schedule LOD200 - Assembly Code: 41.10; Type Image: Raster image: Heraklith Heratekta.jpg; Model: Heraklith® | Heratekta+ is een houtwolcementpaneel gecombineerd met een EPS-plaat.; Manufacturer: Knauf Insulation B.V.; URL: www.heraklith.nl; Description: Heratekta+ - 50mm; phone: +31(0)162-421245; email: customerservice.nl@knaufinsulation.com; product URL: https://heraklith.nl/houtwol-producten/heratekta-met-EPS; warmteweerstand: 1,40 (m2.K/W); NLRS_C_Code_Brandklasse: B-s1,d0; brandweerstand: n.v.t; geluidsabsorbtie: 0,30; DoP: 4010_HERATEKTA+; NLRS_C_content_creator: Knauf Insulation; NLRS_C_content_versie: V1.0
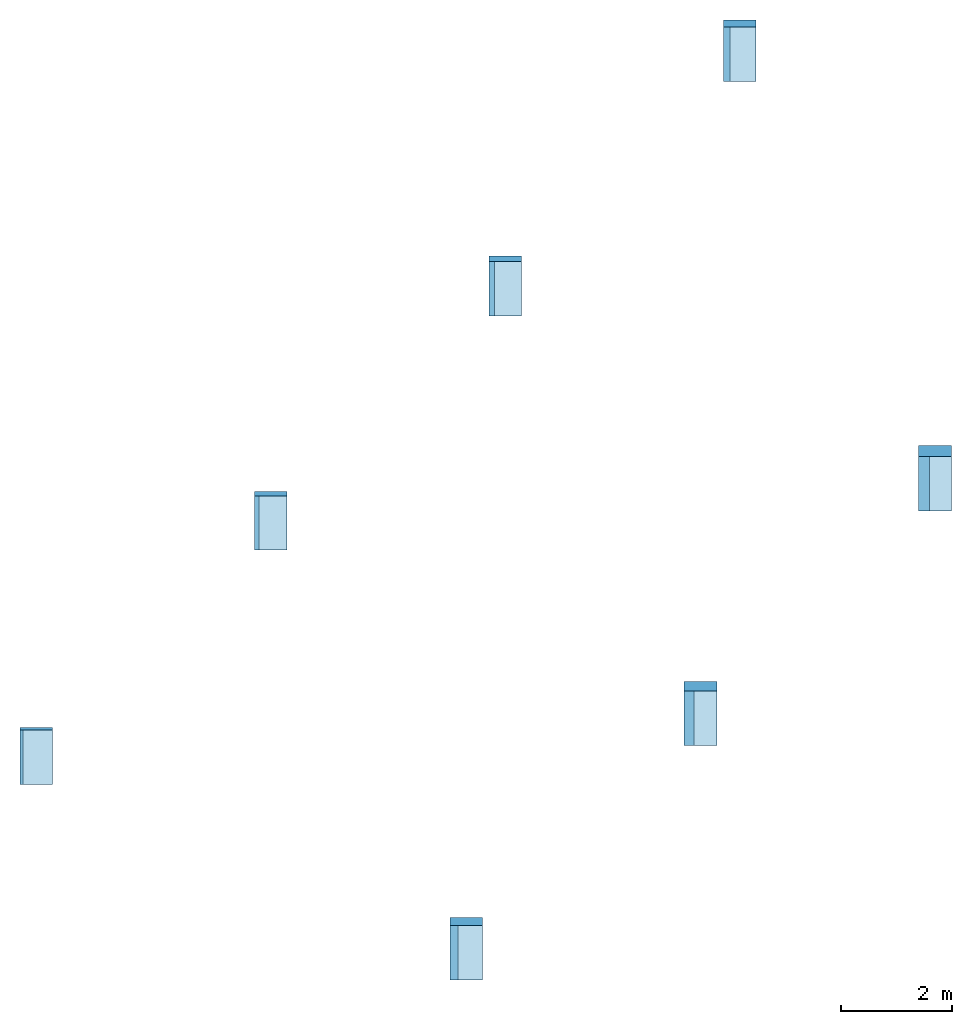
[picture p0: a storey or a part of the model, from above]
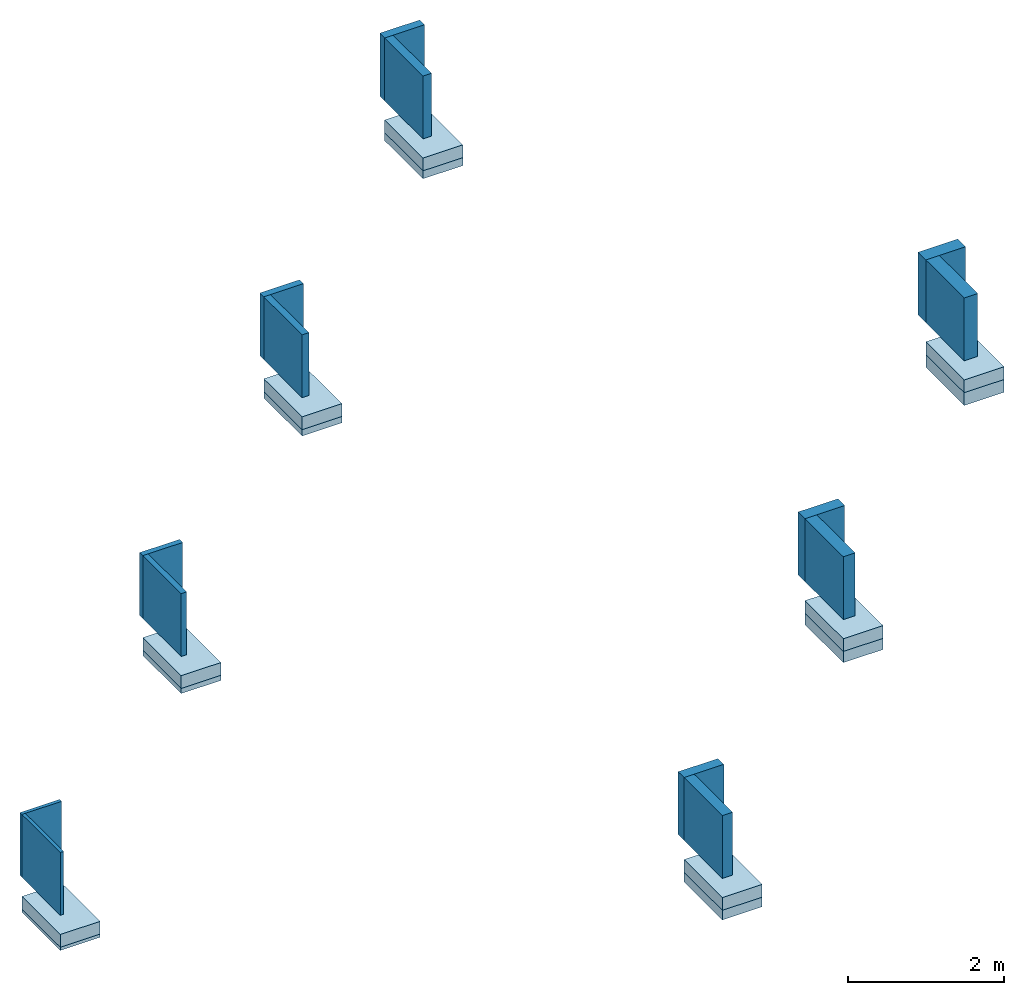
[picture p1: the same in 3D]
Properties of the parts of a building model (IFC2X3), part 2 of 2

# IfcWallStandardCase: Basic Wall:NLRS_41_WA_Heraklith Heratekta+ 50x985x590mm, Basic Wall:NLRS_41_WA_Heraklith Heratekta+ 50x985x590mm:928375
Type - Pset_Wall Schedule LOD400 - gewicht KG/M2: 9; Assembly Code: 41.10; Type Image: Raster image: Heraklith Heratekta.jpg; Model: Heraklith® | Heratekta+ is een houtwolcementpaneel gecombineerd met een EPS-plaat.; Manufacturer: Knauf Insulation B.V.; URL: www.heraklith.nl; Description: Heratekta+ - 50mm; phone: +31(0)162-421245; email: customerservice.nl@knaufinsulation.com; product URL: https://heraklith.nl/houtwol-producten/heratekta-met-EPS; warmteweerstand: 1,40 (m2.K/W); NLRS_C_Code_Brandklasse: B-s1,d0; brandweerstand: n.v.t; geluidsabsorbtie: 0,30; DoP: 4010_HERATEKTA+; NLRS_C_content_creator: Knauf Insulation; NLRS_C_content_versie: V1.0; panelen per pallet: 44; pallet m2: 25.57 m2; vezelbreedte: standaard 2mm optie: 1mm; kleur: standaard naturel optie: Wit (RAL9003) / RAL; Druksterkte kPa: 40; Chloride gehalte: Cl1; Tolerantie: Dikte (T): (T1) +3/-2; Tolerantie: Lengte (L): (L2) +3/-5; Tolerantie: Breedte (W): (W1) +3/-3; Tolerantie: Haaksheid (S): (S1) ≤4; Tolerantie: Vlakheid (P): (P1) ≤6; Randafwerking: Isolatie: tand en groef; Randafwerking: Houtwol: Facet: 5mm; CE-codering: WW-C/2 EPS-EN13168-L2-W1-S1-T1-P1-CS(10/Y)40-Cl1
Classification: 41.10 (Uniformat)
Pset_WallCommon - ExtendToStructure: no; LoadBearing: no; IsExternal: yes
Wall Schedule LOD200 - Type: Basic Wall: NLRS_41_WA_Heraklith Heratekta+ 50x985x590mm
Pset_Wall Schedule LOD400 - Type: Basic Wall: NLRS_41_WA_Heraklith Heratekta+ 50x985x590mm

# IfcWallStandardCase: Basic Wall:NLRS_41_WA_Heraklith Heratekta+ 80x985x590mm, Basic Wall:NLRS_41_WA_Heraklith Heratekta+ 80x985x590mm:930062
In: 00 begane grond
Type - PredefinedType: STANDARD; Material: Heraklith® I Heratekta - EPS60-SE 70 mm, Heraklith® | Heratekta - Houtwollaag - 985x590mm 10 mm
Type - Pset_ElementShading - Roughness: 304.8 mm
Type - Pset_ManufacturerTypeInformation - Manufacturer: Knauf Insulation B.V.
Type - Pset_ProductRequirements - Category: Walls
Type - Pset_QuantityTakeOff - Reference: Basic Wall:NLRS_41_WA_Heraklith Heratekta+ 80x985x590mm
Type - Pset_ReinforcementBarPitchOfWall - Description: Heratekta+ - 80mm; Reference: Basic Wall:NLRS_41_WA_Heraklith Heratekta+ 80x985x590mm
Type - Pset_WallCommon - IsExternal: no; Reference: Basic Wall:NLRS_41_WA_Heraklith Heratekta+ 80x985x590mm; ThermalTransmittance: 0.435045 kg/K/s3
Type - Wall Schedule LOD200 - Assembly Code: 41.10; Type Image: Raster image: Heraklith Heratekta.jpg; Model: Heraklith® | Heratekta+ is een houtwolcementpaneel gecombineerd met een EPS-plaat.; Manufacturer: Knauf Insulation B.V.; URL: www.heraklith.nl; Description: Heratekta+ - 80mm; phone: +31(0)162-421245; email: customerservice.nl@knaufinsulation.com; product URL: https://heraklith.nl/houtwol-producten/heratekta-met-EPS; warmteweerstand: 2,35 (m2.K/W); NLRS_C_Code_Brandklasse: B-s1,d0; brandweerstand: n.v.t; geluidsabsorbtie: 0,30; DoP: 4010_HERATEKTA+; NLRS_C_content_creator: Knauf Insulation; NLRS_C_content_versie: V1.0
Type - Pset_Wall Schedule LOD400 - Assembly Code: 41.10; Type Image: Raster image: Heraklith Heratekta.jpg; Model: Heraklith® | Heratekta+ is een houtwolcementpaneel gecombineerd met een EPS-plaat.; Manufacturer: Knauf Insulation B.V.; URL: www.heraklith.nl; Description: Heratekta+ - 80mm; phone: +31(0)162-421245; email: customerservice.nl@knaufinsulation.com; product URL: https://heraklith.nl/houtwol-producten/heratekta-met-EPS; warmteweerstand: 2,35 (m2.K/W); NLRS_C_Code_Brandklasse: B-s1,d0; brandweerstand: n.v.t; geluidsabsorbtie: 0,30; DoP: 4010_HERATEKTA+; NLRS_C_content_creator: Knauf Insulation; NLRS_C_content_versie: V1.0; gewicht KG/M2: 9.4; panelen per pallet: 26; pallet m2: 15.11 m2; vezelbreedte: standaard 2mm optie: 1mm; kleur: standaard naturel optie: Wit (RAL9003) / RAL; Druksterkte kPa: 40; Chloride gehalte: Cl1; Tolerantie: Dikte (T): (T1) +3/-2; Tolerantie: Lengte (L): (L2) +3/-5; Tolerantie: Breedte (W): (W1) +3/-3; Tolerantie: Haaksheid (S): (S1) ≤4; Tolerantie: Vlakheid (P): (P1) ≤6; Randafwerking: Isolatie: tand en groef; Randafwerking: Houtwol: Facet: 5mm; CE-codering: WW-C/2 EPS-EN13168-L2-W1-S1-T1-P1-CS(10/Y)40-Cl1
Classification: 41.10 (Uniformat)
Pset_WallCommon - ExtendToStructure: no; LoadBearing: no; IsExternal: yes
Wall Schedule LOD200 - Type: Basic Wall: NLRS_41_WA_Heraklith Heratekta+ 80x985x590mm
Pset_Wall Schedule LOD400 - Type: Basic Wall: NLRS_41_WA_Heraklith Heratekta+ 80x985x590mm

# IfcWallStandardCase: Basic Wall:NLRS_42_WA_Heraklith Heratekta+ 100x985x590mm, Basic Wall:NLRS_42_WA_Heraklith Heratekta+ 100x985x590mm:930201
In: 00 begane grond
Type - PredefinedType: STANDARD; Material: Heraklith® I Heratekta - EPS60-SE 90 mm, Heraklith® | Heratekta - Houtwollaag - 985x590mm 10 mm
Type - Pset_ElementShading - Roughness: 304.8 mm
Type - Pset_ManufacturerTypeInformation - Manufacturer: Knauf Insulation B.V.
Type - Pset_ProductRequirements - Category: Walls
Type - Pset_QuantityTakeOff - Reference: Basic Wall:NLRS_42_WA_Heraklith Heratekta+ 100x985x590mm
Type - Pset_ReinforcementBarPitchOfWall - Description: Heratekta+ - 100mm; Reference: Basic Wall:NLRS_42_WA_Heraklith Heratekta+ 100x985x590mm
Type - Pset_WallCommon - IsExternal: no; Reference: Basic Wall:NLRS_42_WA_Heraklith Heratekta+ 100x985x590mm; ThermalTransmittance: 0.342043 kg/K/s3
Type - Wall Schedule LOD200 - Assembly Code: 42.10; Type Image: Raster image: Heraklith Heratekta.jpg; Model: Heraklith® | Heratekta+ is een houtwolcementpaneel gecombineerd met een EPS-plaat.; Manufacturer: Knauf Insulation B.V.; URL: www.heraklith.nl; Description: Heratekta+ - 100mm; phone: +31(0)162-421245; email: customerservice.nl@knaufinsulation.com; product URL: https://heraklith.nl/houtwol-producten/heratekta-met-EPS; warmteweerstand: 3,00 (m2.K/W); NLRS_C_Code_Brandklasse: B-s1,d0; brandweerstand: n.v.t; geluidsabsorbtie: 0,30; DoP: 4010_HERATEKTA+; NLRS_C_content_creator: Knauf Insulation; NLRS_C_content_versie: V1.0
Type - Pset_Wall Schedule LOD400 - Assembly Code: 42.10; Type Image: Raster image: Heraklith Heratekta.jpg; Model: Heraklith® | Heratekta+ is een houtwolcementpaneel gecombineerd met een EPS-plaat.; Manufacturer: Knauf Insulation B.V.; URL: www.heraklith.nl; Description: Heratekta+ - 100mm; phone: +31(0)162-421245; email: customerservice.nl@knaufinsulation.com; product URL: https://heraklith.nl/houtwol-producten/heratekta-met-EPS; warmteweerstand: 3,00 (m2.K/W); NLRS_C_Code_Brandklasse: B-s1,d0; brandweerstand: n.v.t; geluidsabsorbtie: 0,30; DoP: 4010_HERATEKTA+; NLRS_C_content_creator: Knauf Insulation; NLRS_C_content_versie: V1.0; gewicht KG/M2: 9.7; panelen per pallet: 22; pallet m2: 12.79 m2; vezelbreedte: standaard 2mm optie: 1mm; kleur: standaard naturel optie: Wit (RAL9003) / RAL; Druksterkte kPa: 40; Chloride gehalte: Cl1; Tolerantie: Dikte (T): (T1) +3/-2; Tolerantie: Lengte (L): (L2) +3/-5; Tolerantie: Breedte (W): (W1) +3/-3; Tolerantie: Haaksheid (S): (S1) ≤4; Tolerantie: Vlakheid (P): (P1) ≤6; Randafwerking: Isolatie: tand en groef; Randafwerking: Houtwol: Facet: 5mm; CE-codering: WW-C/2 EPS-EN13168-L2-W1-S1-T1-P1-CS(10/Y)40-Cl1
Classification: 42.10 (Uniformat)
Pset_WallCommon - ExtendToStructure: no; LoadBearing: no
Wall Schedule LOD200 - Type: Basic Wall: NLRS_42_WA_Heraklith Heratekta+ 100x985x590mm
Pset_Wall Schedule LOD400 - Type: Basic Wall: NLRS_42_WA_Heraklith Heratekta+ 100x985x590mm

# IfcWallStandardCase: Basic Wall:NLRS_42_WA_Heraklith Heratekta+ 125x985x590mm, Basic Wall:NLRS_42_WA_Heraklith Heratekta+ 125x985x590mm:930361
In: 00 begane grond
Type - PredefinedType: STANDARD; Material: Heraklith® I Heratekta - EPS60-SE 115 mm, Heraklith® | Heratekta - Houtwollaag - 985x590mm 10 mm
Type - Pset_ElementShading - Roughness: 304.8 mm
Type - Pset_ManufacturerTypeInformation - Manufacturer: Knauf Insulation B.V.
Type - Pset_ProductRequirements - Category: Walls
Type - Pset_QuantityTakeOff - Reference: Basic Wall:NLRS_42_WA_Heraklith Heratekta+ 125x985x590mm
Type - Pset_ReinforcementBarPitchOfWall - Description: Heratekta+ - 125mm; Reference: Basic Wall:NLRS_42_WA_Heraklith Heratekta+ 125x985x590mm
Type - Pset_WallCommon - IsExternal: no; Reference: Basic Wall:NLRS_42_WA_Heraklith Heratekta+ 125x985x590mm; ThermalTransmittance: 0.269916 kg/K/s3
Type - Wall Schedule LOD200 - Assembly Code: 42.10; Type Image: Raster image: Heraklith Heratekta.jpg; Model: Heraklith® | Heratekta+ is een houtwolcementpaneel gecombineerd met een EPS-plaat.; Manufacturer: Knauf Insulation B.V.; URL: www.heraklith.nl; Description: Heratekta+ - 125mm; phone: +31(0)162-421245; email: customerservice.nl@knaufinsulation.com; product URL: https://heraklith.nl/houtwol-producten/heratekta-met-EPS; warmteweerstand: 3,80 (m2.K/W); NLRS_C_Code_Brandklasse: B-s1,d0; brandweerstand: n.v.t; geluidsabsorbtie: 0,30; DoP: 4010_HERATEKTA+; NLRS_C_content_creator: Knauf Insulation; NLRS_C_content_versie: V1.0
Type - Pset_Wall Schedule LOD400 - gewicht KG/M2: 10; Assembly Code: 42.10; Type Image: Raster image: Heraklith Heratekta.jpg; Model: Heraklith® | Heratekta+ is een houtwolcementpaneel gecombineerd met een EPS-plaat.; Manufacturer: Knauf Insulation B.V.; URL: www.heraklith.nl; Description: Heratekta+ - 125mm; phone: +31(0)162-421245; email: customerservice.nl@knaufinsulation.com; product URL: https://heraklith.nl/houtwol-producten/heratekta-met-EPS; warmteweerstand: 3,80 (m2.K/W); NLRS_C_Code_Brandklasse: B-s1,d0; brandweerstand: n.v.t; geluidsabsorbtie: 0,30; DoP: 4010_HERATEKTA+; NLRS_C_content_creator: Knauf Insulation; NLRS_C_content_versie: V1.0; panelen per pallet: 18; pallet m2: 10.46 m2; vezelbreedte: standaard 2mm optie: 1mm; kleur: standaard naturel optie: Wit (RAL9003) / RAL; Druksterkte kPa: 40; Chloride gehalte: Cl1; Tolerantie: Dikte (T): (T1) +3/-2; Tolerantie: Lengte (L): (L2) +3/-5; Tolerantie: Breedte (W): (W1) +3/-3; Tolerantie: Haaksheid (S): (S1) ≤4; Tolerantie: Vlakheid (P): (P1) ≤6; Randafwerking: Isolatie: tand en groef; Randafwerking: Houtwol: Facet: 5mm; CE-codering: WW-C/2 EPS-EN13168-L2-W1-S1-T1-P1-CS(10/Y)40-Cl1
Classification: 42.10 (Uniformat)
Pset_WallCommon - ExtendToStructure: no; LoadBearing: no
Wall Schedule LOD200 - Type: Basic Wall: NLRS_42_WA_Heraklith Heratekta+ 125x985x590mm
Pset_Wall Schedule LOD400 - Type: Basic Wall: NLRS_42_WA_Heraklith Heratekta+ 125x985x590mm

# IfcWallStandardCase: Basic Wall:NLRS_42_WA_Heraklith Heratekta+ 150x985x590mm, Basic Wall:NLRS_42_WA_Heraklith Heratekta+ 150x985x590mm:930601
In: 00 begane grond
Type - PredefinedType: STANDARD; Material: Heraklith® I Heratekta - EPS60-SE 140 mm, Heraklith® | Heratekta - Houtwollaag - 985x590mm 10 mm
Type - Pset_ElementShading - Roughness: 304.8 mm
Type - Pset_ManufacturerTypeInformation - Manufacturer: Knauf Insulation B.V.
Type - Pset_ProductRequirements - Category: Walls
Type - Pset_QuantityTakeOff - Reference: Basic Wall:NLRS_42_WA_Heraklith Heratekta+ 150x985x590mm
Type - Pset_ReinforcementBarPitchOfWall - Description: Heratekta+ - 150mm; Reference: Basic Wall:NLRS_42_WA_Heraklith Heratekta+ 150x985x590mm
Type - Pset_WallCommon - IsExternal: no; Reference: Basic Wall:NLRS_42_WA_Heraklith Heratekta+ 150x985x590mm; ThermalTransmittance: 0.22291 kg/K/s3
Type - Wall Schedule LOD200 - Assembly Code: 42.10; Type Image: Raster image: Heraklith Heratekta.jpg; Model: Heraklith® | Heratekta+ is een houtwolcementpaneel gecombineerd met een EPS-plaat.; Manufacturer: Knauf Insulation B.V.; URL: www.heraklith.nl; Description: Heratekta+ - 150mm; phone: +31(0)162-421245; email: customerservice.nl@knaufinsulation.com; product URL: https://heraklith.nl/houtwol-producten/heratekta-met-EPS; warmteweerstand: 4,60 (m2.K/W); NLRS_C_Code_Brandklasse: B-s1,d0; brandweerstand: n.v.t; geluidsabsorbtie: 0,30; DoP: 4010_HERATEKTA+; NLRS_C_content_creator: Knauf Insulation; NLRS_C_content_versie: V1.0
Type - Pset_Wall Schedule LOD400 - Assembly Code: 42.10; Type Image: Raster image: Heraklith Heratekta.jpg; Model: Heraklith® | Heratekta+ is een houtwolcementpaneel gecombineerd met een EPS-plaat.; Manufacturer: Knauf Insulation B.V.; URL: www.heraklith.nl; Description: Heratekta+ - 150mm; phone: +31(0)162-421245; email: customerservice.nl@knaufinsulation.com; product URL: https://heraklith.nl/houtwol-producten/heratekta-met-EPS; warmteweerstand: 4,60 (m2.K/W); NLRS_C_Code_Brandklasse: B-s1,d0; brandweerstand: n.v.t; geluidsabsorbtie: 0,30; DoP: 4010_HERATEKTA+; NLRS_C_content_creator: Knauf Insulation; NLRS_C_content_versie: V1.0; gewicht KG/M2: 10.4; panelen per pallet: 14; pallet m2: 8.14 m2; vezelbreedte: standaard 2mm optie: 1mm; kleur: standaard naturel optie: Wit (RAL9003) / RAL; Druksterkte kPa: 40; Chloride gehalte: Cl1; Tolerantie: Dikte (T): (T1) +3/-2; Tolerantie: Lengte (L): (L2) +3/-5; Tolerantie: Breedte (W): (W1) +3/-3; Tolerantie: Haaksheid (S): (S1) ≤4; Tolerantie: Vlakheid (P): (P1) ≤6; Randafwerking: Isolatie: tand en groef; Randafwerking: Houtwol: Facet: 5mm; CE-codering: WW-C/2 EPS-EN13168-L2-W1-S1-T1-P1-CS(10/Y)40-Cl1
Classification: 42.10 (Uniformat)
Pset_WallCommon - ExtendToStructure: no; LoadBearing: no
Wall Schedule LOD200 - Type: Basic Wall: NLRS_42_WA_Heraklith Heratekta+ 150x985x590mm
Pset_Wall Schedule LOD400 - Type: Basic Wall: NLRS_42_WA_Heraklith Heratekta+ 150x985x590mm

# IfcWallStandardCase: Basic Wall:NLRS_42_WA_Heraklith Heratekta+ 175x985x590mm, Basic Wall:NLRS_42_WA_Heraklith Heratekta+ 175x985x590mm:930701
In: 00 begane grond
Type - PredefinedType: STANDARD; Material: Heraklith® I Heratekta - EPS60-SE 165 mm, Heraklith® | Heratekta - Houtwollaag - 985x590mm 10 mm
Type - Pset_ElementShading - Roughness: 304.8 mm
Type - Pset_ManufacturerTypeInformation - Manufacturer: Knauf Insulation B.V.
Type - Pset_ProductRequirements - Category: Walls
Type - Pset_QuantityTakeOff - Reference: Basic Wall:NLRS_42_WA_Heraklith Heratekta+ 175x985x590mm
Type - Pset_ReinforcementBarPitchOfWall - Description: Heratekta+ - 175mm; Reference: Basic Wall:NLRS_42_WA_Heraklith Heratekta+ 175x985x590mm
Type - Pset_WallCommon - IsExternal: no; Reference: Basic Wall:NLRS_42_WA_Heraklith Heratekta+ 175x985x590mm; ThermalTransmittance: 0.189848 kg/K/s3
Type - Wall Schedule LOD200 - Assembly Code: 42.10; Type Image: Raster image: Heraklith Heratekta.jpg; Model: Heraklith® | Heratekta+ is een houtwolcementpaneel gecombineerd met een EPS-plaat.; Manufacturer: Knauf Insulation B.V.; URL: www.heraklith.nl; Description: Heratekta+ - 175mm; phone: +31(0)162-421245; email: customerservice.nl@knaufinsulation.com; product URL: https://heraklith.nl/houtwol-producten/heratekta-met-EPS; warmteweerstand: 5,40 (m2.K/W); NLRS_C_Code_Brandklasse: B-s1,d0; brandweerstand: n.v.t; geluidsabsorbtie: 0,30; DoP: 4010_HERATEKTA+; NLRS_C_content_creator: Knauf Insulation; NLRS_C_content_versie: V1.0
Type - Pset_Wall Schedule LOD400 - Assembly Code: 42.10; Type Image: Raster image: Heraklith Heratekta.jpg; Model: Heraklith® | Heratekta+ is een houtwolcementpaneel gecombineerd met een EPS-plaat.; Manufacturer: Knauf Insulation B.V.; URL: www.heraklith.nl; Description: Heratekta+ - 175mm; phone: +31(0)162-421245; email: customerservice.nl@knaufinsulation.com; product URL: https://heraklith.nl/houtwol-producten/heratekta-met-EPS; warmteweerstand: 5,40 (m2.K/W); NLRS_C_Code_Brandklasse: B-s1,d0; brandweerstand: n.v.t; geluidsabsorbtie: 0,30; DoP: 4010_HERATEKTA+; NLRS_C_content_creator: Knauf Insulation; NLRS_C_content_versie: V1.0; gewicht KG/M2: 10.7; panelen per pallet: 12; pallet m2: 6.97 m2; vezelbreedte: standaard 2mm optie: 1mm; kleur: standaard naturel optie: Wit (RAL9003) / RAL; Druksterkte kPa: 40; Chloride gehalte: Cl1; Tolerantie: Dikte (T): (T1) +3/-2; Tolerantie: Lengte (L): (L2) +3/-5; Tolerantie: Breedte (W): (W1) +3/-3; Tolerantie: Haaksheid (S): (S1) ≤4; Tolerantie: Vlakheid (P): (P1) ≤6; Randafwerking: Isolatie: tand en groef; Randafwerking: Houtwol: Facet: 5mm; CE-codering: WW-C/2 EPS-EN13168-L2-W1-S1-T1-P1-CS(10/Y)40-Cl1
Classification: 42.10 (Uniformat)
Pset_WallCommon - ExtendToStructure: no; LoadBearing: no
Wall Schedule LOD200 - Type: Basic Wall: NLRS_42_WA_Heraklith Heratekta+ 175x985x590mm
Pset_Wall Schedule LOD400 - Type: Basic Wall: NLRS_42_WA_Heraklith Heratekta+ 175x985x590mm

# IfcWallStandardCase: Basic Wall:NLRS_42_WA_Heraklith Heratekta+ 200x985x590mm, Basic Wall:NLRS_42_WA_Heraklith Heratekta+ 200x985x590mm:930881
In: 00 begane grond
Type - PredefinedType: STANDARD; Material: Heraklith® I Heratekta - EPS60-SE 190 mm, Heraklith® | Heratekta - Houtwollaag - 985x590mm 10 mm
Type - Pset_ElementShading - Roughness: 304.8 mm
Type - Pset_ManufacturerTypeInformation - Manufacturer: Knauf Insulation B.V.
Type - Pset_ProductRequirements - Category: Walls
Type - Pset_QuantityTakeOff - Reference: Basic Wall:NLRS_42_WA_Heraklith Heratekta+ 200x985x590mm
Type - Pset_ReinforcementBarPitchOfWall - Description: Heratekta+ - 200mm; Reference: Basic Wall:NLRS_42_WA_Heraklith Heratekta+ 200x985x590mm
Type - Pset_WallCommon - IsExternal: no; Reference: Basic Wall:NLRS_42_WA_Heraklith Heratekta+ 200x985x590mm; ThermalTransmittance: 0.165327 kg/K/s3
Type - Wall Schedule LOD200 - Assembly Code: 42.10; Type Image: Raster image: Heraklith Heratekta.jpg; Model: Heraklith® | Heratekta+ is een houtwolcementpaneel gecombineerd met een EPS-plaat.; Manufacturer: Knauf Insulation B.V.; URL: www.heraklith.nl; Description: Heratekta+ - 200mm; phone: +31(0)162-421245; email: customerservice.nl@knaufinsulation.com; product URL: https://heraklith.nl/houtwol-producten/heratekta-met-EPS; warmteweerstand: 6,20 (m2.K/W); NLRS_C_Code_Brandklasse: B-s1,d0; brandweerstand: n.v.t; geluidsabsorbtie: 0,30; DoP: 4010_HERATEKTA+; NLRS_C_content_creator: Knauf Insulation; NLRS_C_content_versie: V1.0
Type - Pset_Wall Schedule LOD400 - panelen per pallet: 10; Assembly Code: 42.10; Type Image: Raster image: Heraklith Heratekta.jpg; Model: Heraklith® | Heratekta+ is een houtwolcementpaneel gecombineerd met een EPS-plaat.; Manufacturer: Knauf Insulation B.V.; URL: www.heraklith.nl; Description: Heratekta+ - 200mm; phone: +31(0)162-421245; email: customerservice.nl@knaufinsulation.com; product URL: https://heraklith.nl/houtwol-producten/heratekta-met-EPS; warmteweerstand: 6,20 (m2.K/W); NLRS_C_Code_Brandklasse: B-s1,d0; brandweerstand: n.v.t; geluidsabsorbtie: 0,30; DoP: 4010_HERATEKTA+; NLRS_C_content_creator: Knauf Insulation; NLRS_C_content_versie: V1.0; gewicht KG/M2: 11.1; pallet m2: 5.81 m2; vezelbreedte: standaard 2mm optie: 1mm; kleur: standaard naturel optie: Wit (RAL9003) / RAL; Druksterkte kPa: 40; Chloride gehalte: Cl1; Tolerantie: Dikte (T): (T1) +3/-2; Tolerantie: Lengte (L): (L2) +3/-5; Tolerantie: Breedte (W): (W1) +3/-3; Tolerantie: Haaksheid (S): (S1) ≤4; Tolerantie: Vlakheid (P): (P1) ≤6; Randafwerking: Isolatie: tand en groef; Randafwerking: Houtwol: Facet: 5mm; CE-codering: WW-C/2 EPS-EN13168-L2-W1-S1-T1-P1-CS(10/Y)40-Cl1
Classification: 42.10 (Uniformat)
Pset_WallCommon - ExtendToStructure: no; LoadBearing: no
Wall Schedule LOD200 - Type: Basic Wall: NLRS_42_WA_Heraklith Heratekta+ 200x985x590mm
Pset_Wall Schedule LOD400 - Type: Basic Wall: NLRS_42_WA_Heraklith Heratekta+ 200x985x590mm

# IfcWallStandardCase: Basic Wall:NLRS_42_WA_Heraklith Heratekta+ 50x985x590mm, Basic Wall:NLRS_42_WA_Heraklith Heratekta+ 50x985x590mm:928297
In: 00 begane grond
Type - PredefinedType: STANDARD; Material: Heraklith® I Heratekta - EPS60-SE 40 mm, Heraklith® | Heratekta - Houtwollaag - 985x590mm 10 mm
Type - Pset_ElementShading - Roughness: 304.8 mm
Type - Pset_ManufacturerTypeInformation - Manufacturer: Knauf Insulation B.V.
Type - Pset_ProductRequirements - Category: Walls
Type - Pset_QuantityTakeOff - Reference: Basic Wall:NLRS_42_WA_Heraklith Heratekta+ 50x985x590mm
Type - Pset_ReinforcementBarPitchOfWall - Description: Heratekta+ - 50mm; Reference: Basic Wall:NLRS_42_WA_Heraklith Heratekta+ 50x985x590mm
Type - Pset_WallCommon - Reference: Basic Wall:NLRS_42_WA_Heraklith Heratekta+ 50x985x590mm; ThermalTransmittance: 0.734694 kg/K/s3; IsExternal: no
Type - Wall Schedule LOD200 - Assembly Code: 42.10; Type Image: Raster image: Heraklith Heratekta.jpg; Model: Heraklith® | Heratekta+ is een houtwolcementpaneel gecombineerd met een EPS-plaat.; Manufacturer: Knauf Insulation B.V.; URL: www.heraklith.nl; Description: Heratekta+ - 50mm; phone: +31(0)162-421245; email: customerservice.nl@knaufinsulation.com; product URL: https://heraklith.nl/houtwol-producten/heratekta-met-EPS; warmteweerstand: 1,40 (m2.K/W); NLRS_C_Code_Brandklasse: B-s1,d0; brandweerstand: n.v.t; geluidsabsorbtie: 0,30; DoP: 4010_HERATEKTA+; NLRS_C_content_creator: Knauf Insulation; NLRS_C_content_versie: V1.0
Type - Pset_Wall Schedule LOD400 - gewicht KG/M2: 9; Assembly Code: 42.10; Type Image: Raster image: Heraklith Heratekta.jpg; Model: Heraklith® | Heratekta+ is een houtwolcementpaneel gecombineerd met een EPS-plaat.; Manufacturer: Knauf Insulation B.V.; URL: www.heraklith.nl; Description: Heratekta+ - 50mm; phone: +31(0)162-421245; email: customerservice.nl@knaufinsulation.com; product URL: https://heraklith.nl/houtwol-producten/heratekta-met-EPS; warmteweerstand: 1,40 (m2.K/W); NLRS_C_Code_Brandklasse: B-s1,d0; brandweerstand: n.v.t; geluidsabsorbtie: 0,30; DoP: 4010_HERATEKTA+; NLRS_C_content_creator: Knauf Insulation; NLRS_C_content_versie: V1.0; panelen per pallet: 44; pallet m2: 25.57 m2; vezelbreedte: standaard 2mm optie: 1mm; kleur: standaard naturel optie: Wit (RAL9003) / RAL; Druksterkte kPa: 40; Chloride gehalte: Cl1; Tolerantie: Dikte (T): (T1) +3/-2; Tolerantie: Lengte (L): (L2) +3/-5; Tolerantie: Breedte (W): (W1) +3/-3; Tolerantie: Haaksheid (S): (S1) ≤4; Tolerantie: Vlakheid (P): (P1) ≤6; Randafwerking: Isolatie: tand en groef; Randafwerking: Houtwol: Facet: 5mm; CE-codering: WW-C/2 EPS-EN13168-L2-W1-S1-T1-P1-CS(10/Y)40-Cl1
Classification: 42.10 (Uniformat)
Pset_WallCommon - ExtendToStructure: no; LoadBearing: no
Wall Schedule LOD200 - Type: Basic Wall: NLRS_42_WA_Heraklith Heratekta+ 50x985x590mm
Pset_Wall Schedule LOD400 - Type: Basic Wall: NLRS_42_WA_Heraklith Heratekta+ 50x985x590mm

# IfcWallStandardCase: Basic Wall:NLRS_42_WA_Heraklith Heratekta+ 80x985x590mm, Basic Wall:NLRS_42_WA_Heraklith Heratekta+ 80x985x590mm:930061
In: 00 begane grond
Type - PredefinedType: STANDARD; Material: Heraklith® I Heratekta - EPS60-SE 70 mm, Heraklith® | Heratekta - Houtwollaag - 985x590mm 10 mm
Type - Pset_ElementShading - Roughness: 304.8 mm
Type - Pset_ManufacturerTypeInformation - Manufacturer: Knauf Insulation B.V.
Type - Pset_ProductRequirements - Category: Walls
Type - Pset_QuantityTakeOff - Reference: Basic Wall:NLRS_42_WA_Heraklith Heratekta+ 80x985x590mm
Type - Pset_ReinforcementBarPitchOfWall - Description: Heratekta+ - 80mm; Reference: Basic Wall:NLRS_42_WA_Heraklith Heratekta+ 80x985x590mm
Type - Pset_WallCommon - IsExternal: no; Reference: Basic Wall:NLRS_42_WA_Heraklith Heratekta+ 80x985x590mm; ThermalTransmittance: 0.435045 kg/K/s3
Type - Wall Schedule LOD200 - Assembly Code: 42.10; Type Image: Raster image: Heraklith Heratekta.jpg; Model: Heraklith® | Heratekta+ is een houtwolcementpaneel gecombineerd met een EPS-plaat.; Manufacturer: Knauf Insulation B.V.; URL: www.heraklith.nl; Description: Heratekta+ - 80mm; phone: +31(0)162-421245; email: customerservice.nl@knaufinsulation.com; product URL: https://heraklith.nl/houtwol-producten/heratekta-met-EPS; warmteweerstand: 2,35 (m2.K/W); NLRS_C_Code_Brandklasse: B-s1,d0; brandweerstand: n.v.t; geluidsabsorbtie: 0,30; DoP: 4010_HERATEKTA+; NLRS_C_content_creator: Knauf Insulation; NLRS_C_content_versie: V1.0
Type - Pset_Wall Schedule LOD400 - Assembly Code: 42.10; Type Image: Raster image: Heraklith Heratekta.jpg; Model: Heraklith® | Heratekta+ is een houtwolcementpaneel gecombineerd met een EPS-plaat.; Manufacturer: Knauf Insulation B.V.; URL: www.heraklith.nl; Description: Heratekta+ - 80mm; phone: +31(0)162-421245; email: customerservice.nl@knaufinsulation.com; product URL: https://heraklith.nl/houtwol-producten/heratekta-met-EPS; warmteweerstand: 2,35 (m2.K/W); NLRS_C_Code_Brandklasse: B-s1,d0; brandweerstand: n.v.t; geluidsabsorbtie: 0,30; DoP: 4010_HERATEKTA+; NLRS_C_content_creator: Knauf Insulation; NLRS_C_content_versie: V1.0; gewicht KG/M2: 9.4; panelen per pallet: 26; pallet m2: 15.11 m2; vezelbreedte: standaard 2mm optie: 1mm; kleur: standaard naturel optie: Wit (RAL9003) / RAL; Druksterkte kPa: 40; Chloride gehalte: Cl1; Tolerantie: Dikte (T): (T1) +3/-2; Tolerantie: Lengte (L): (L2) +3/-5; Tolerantie: Breedte (W): (W1) +3/-3; Tolerantie: Haaksheid (S): (S1) ≤4; Tolerantie: Vlakheid (P): (P1) ≤6; Randafwerking: Isolatie: tand en groef; Randafwerking: Houtwol: Facet: 5mm; CE-codering: WW-C/2 EPS-EN13168-L2-W1-S1-T1-P1-CS(10/Y)40-Cl1
Classification: 42.10 (Uniformat)
Pset_WallCommon - ExtendToStructure: no; LoadBearing: no
Wall Schedule LOD200 - Type: Basic Wall: NLRS_42_WA_Heraklith Heratekta+ 80x985x590mm
Pset_Wall Schedule LOD400 - Type: Basic Wall: NLRS_42_WA_Heraklith Heratekta+ 80x985x590mm
